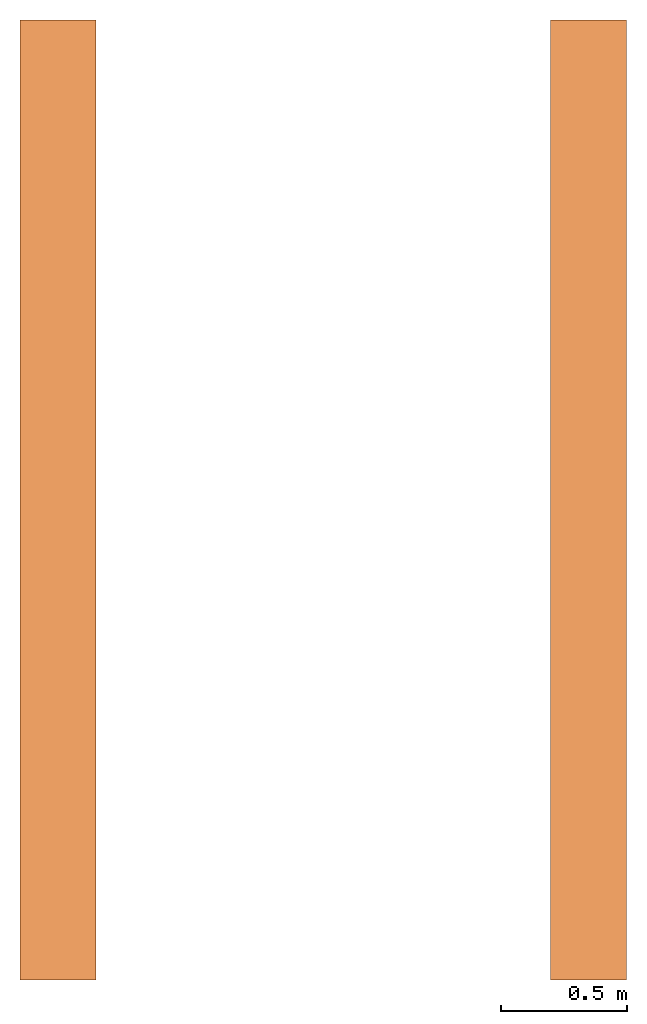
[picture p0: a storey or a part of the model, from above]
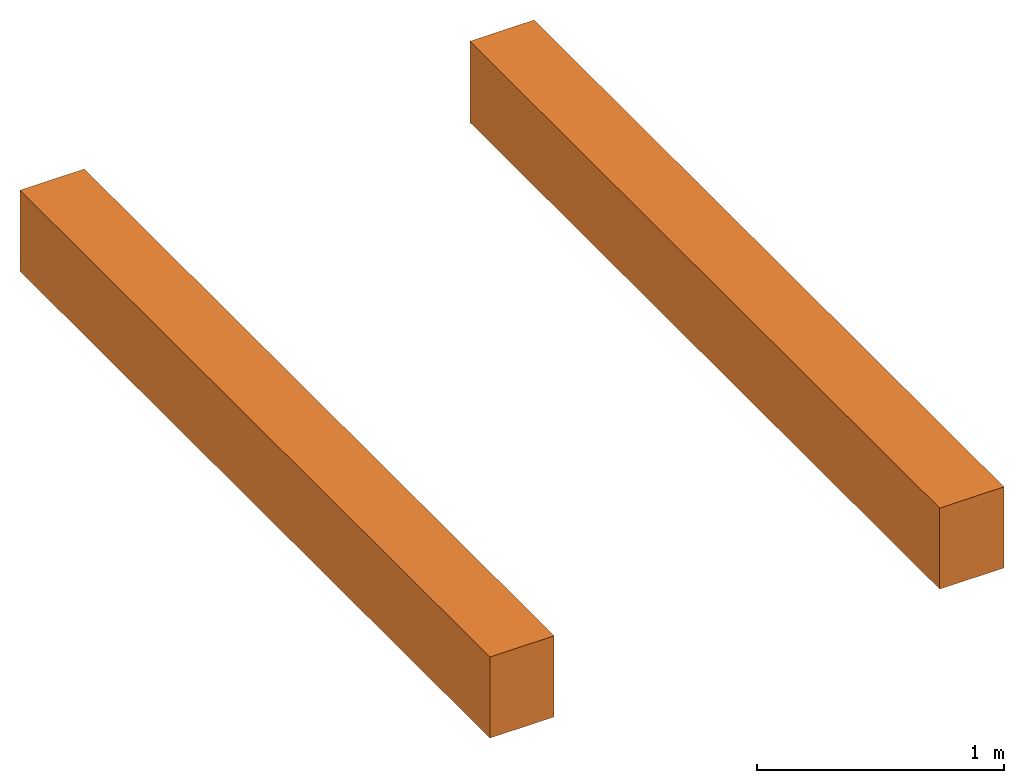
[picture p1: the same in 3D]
Properties of the parts of a building model (IFC2X3), part 1 of 2

# File
Description: ViewDefinition [CoordinationView_V2.0], RevitIdentifiers [ContentGUID: ca527c97-d4ec-411e-be0a-4f397f2c0beb, VersionGUID: 8476af31-6a10-44f1-af04-e6eb835c4134, NumberOfSaves: 289], CoordinateReference [CoordinateBase: Shared Coordinates]
File name: Sandbukta_vba_rvt2024.ifc
Time: 2026-06-26T07:16:23+01:00
Written by: ODA SDAI 24.6
Made in: Autodesk Revit 24.3.20.34 (ENU) - IFC 24.3.50.9

# IfcProject, 1350056494
LongName: Sandbukta VBA; Phase: Anbudsunderlag

# IfcSite, Default
RefLatitude: 59, 54, 44, 239196; RefLongitude: 10, 45, 0, 0; RefElevation: 0 mm

# IfcBuilding, Bygning (endres i Project Information)
LongName: Bygning (endres i Project Information)
Pset_BuildingCommon - NumberOfStoreys: 5

# IfcBuildingStorey: Level:NO_Nivå_Meter-VA (6)
In: Bygning (endres i Project Information)
Pset_AirSideSystemInformation - sets with these values: 2
Name | LongName = Name | Elevation (mm)
Plan U2 - Arbeid | Plan U2 - Arbeid | 11000
Plan U1 - Arbeid | Plan U1 - Arbeid | 14000
Plan arbeidsnivå | Plan arbeidsnivå | 16800
Plan 01 | Plan 01 | 19000
Plan Tak Lav | Plan Tak Lav | 22200
Plan Tak Høy | Plan Tak Høy | 24000

# IfcBuildingElementProxy: Blåsemaskin:Blåsemaskin, Blåsemaskin:Blåsemaskin:2688698
In: Plan 01
Type - Material: <Unnamed>
Pset_BuildingElementProxyCommon - Reference: Blåsemaskin; sets with these values: 2

# IfcBuildingElementProxy: Drenspumpe:Drenspumpe, Drenspumpe:Drenspumpe:2447455
In: Plan U2 - Arbeid
Type - Material: <Unnamed>
Pset_BuildingElementProxyCommon - Reference: Drenspumpe; sets with these values: 2

# IfcBuildingElementProxy: Membranrigg7:Membranrigg, Membranrigg7:Membranrigg:2422887
In: Plan 01
Type - Material: <Unnamed>
Pset_BuildingElementProxyCommon - Reference: Membranrigg; sets with these values: 2

# IfcBuildingElementProxy: Membranrigg8:Membranrigg, Membranrigg8:Membranrigg:2422900
In: Plan 01
Type - Material: <Unnamed>
Pset_BuildingElementProxyCommon - Reference: Membranrigg; sets with these values: 2

# IfcBuildingElementProxy: Overløpsrenne:Overløpsrenne, Overløpsrenne:Overløpsrenne:2651481
In: Plan arbeidsnivå
Type - Material: <Unnamed>
Pset_BuildingElementProxyCommon - Reference: Overløpsrenne; sets with these values: 2

# IfcBuildingElementProxy: Placeholder Luke:100x100cm (5)
In: Plan 01
Type - Material: Default luke
Pset_BuildingElementProxyCommon - Reference: 100x100cm; sets with these values: 2
Name (Placeholder Luke:100x100cm:...)
2450585
2450774
2452067
2452140
2452595

# IfcBuildingElementProxy: Placeholder Luke:200x100cm 2, Placeholder Luke:200x100cm 2:2452269
In: Plan 01
Type - Material: Default luke
Pset_BuildingElementProxyCommon - Reference: 200x100cm 2; sets with these values: 2

# IfcBuildingElementProxy: RNO_CoordinationColumns:RNO_Nullpunktssøyle, RNO_CoordinationColumns:RNO_Nullpunktssøyle:1821742
In: Plan 01
Type - Material: <Unnamed>
Pset_BuildingElementProxyCommon - Reference: RNO_Nullpunktssøyle; sets with these values: 2

# IfcBuildingElementProxy: RNO_CoordinationColumns:RNO_Rotasjonssøyle, RNO_CoordinationColumns:RNO_Rotasjonssøyle:1822006
In: Plan 01
Type - Material: <Unnamed>
Pset_BuildingElementProxyCommon - Reference: RNO_Rotasjonssøyle; sets with these values: 2

# IfcCovering: Basic Ceiling:Ceiling 1, Basic Ceiling:Ceiling 1:2464430
In: Plan 01
Type - PredefinedType: CEILING
Pset_CoveringCommon - Reference: Ceiling 1; sets with these values: 2

# IfcDistributionPort (880)
Description: Flow; FlowDirection: SOURCEANDSINK
Name | Group
Port_2536076_0 | 38= VanGen 2
Port_2536076_1 | 38= VanGen 2
Port_2546204_1 | 38= VanGen 2
Port_2537531_0 | 38= VanGen 2
Port_2688437_2 | 38= VanGen 2
Port_2537531_1 | 38= VanGen 2
Port_2540515_0 | 38= VanGen 3
Port_2650541_1 | 38= VanGen 3
Port_2540515_1 | 38= VanGen 3
Port_2650521_2 | 38= VanGen 3
Port_2544762_0 | 38= VanGen 12
Port_2700529_2 | 38= VanGen 12
Port_2544762_1 | 38= VanGen 12
Port_2700532_2 | 38= VanGen 12
Port_2544801_0 | 38= VanGen 12
Port_2700383_2 | 38= VanGen 12
Port_2544801_1 | 38= VanGen 12
Port_2700387_2 | 38= VanGen 12
Port_2544820_0 | 38= VanGen 12
Port_2700427_2 | 38= VanGen 12
Port_2544820_1 | 38= VanGen 12
Port_2700532_1 | 38= VanGen 12
Port_2546194_0 | 38= VanGen 2
Port_2546204_2 | 38= VanGen 2
Port_2546194_1 | 38= VanGen 2
Port_2546223_1 | 38= VanGen 2
Port_2546223_2 | 38= VanGen 2
Port_2552720_0 | 38= VanGen 2
Port_2547577_0 | 38= VanGen 10
Port_2675238_2 | 38= VanGen 10
Port_2547577_1 | 38= VanGen 10
Port_2675234_3 | 38= VanGen 10
Port_2547586_0 | 38= VanGen 10
Port_2675234_1 | 38= VanGen 10
Port_2547586_1 | 38= VanGen 10
Port_2547589_0 | 38= VanGen 10
Port_2675238_1 | 38= VanGen 10
Port_2547589_1 | 38= VanGen 10
Port_2548496_1 | 38= VanGen 12
Port_2665847_1 | 38= VanGen 12
Port_2548496_2 | 38= VanGen 12
Port_2664733_0 | 38= VanGen 12
Port_2552383_0 | 38= VanGen 2
Port_2614677_2 | 38= VanGen 2
Port_2552383_1 | 38= VanGen 2
Port_2552391_0 | 38= VanGen 2
Port_2614677_1 | 38= VanGen 2
Port_2552391_1 | 38= VanGen 2
Port_2552431_1 | 38= VanGen 2
Port_2552431_2 | 38= VanGen 2
Port_2552611_0 | 38= VanGen 2
Port_2552594_0 | 38= VanGen 2
Port_2552594_1 | 38= VanGen 2
Port_2552614_1 | 38= VanGen 2
Port_2552600_0 | 38= VanGen 2
Port_2552610_3 | 38= VanGen 2
Port_2552600_1 | 38= VanGen 2
Port_2552614_2 | 38= VanGen 2
Port_2552610_1 | 38= VanGen 2
Port_2552646_0 | 38= VanGen 2
Port_2552610_2 | 38= VanGen 2
Port_2552611_1 | 38= VanGen 2
Port_2552646_1 | 38= VanGen 2
Port_2687460_2 | 38= VanGen 2
Port_2552701_0 | 38= VanGen 2
Port_2552701_1 | 38= VanGen 2
Port_2552723_1 | 38= VanGen 2
Port_2552709_0 | 38= VanGen 2
Port_2552719_3 | 38= VanGen 2
Port_2552709_1 | 38= VanGen 2
Port_2552723_2 | 38= VanGen 2
Port_2552719_1 | 38= VanGen 2
Port_2552744_0 | 38= VanGen 2
Port_2552719_2 | 38= VanGen 2
Port_2552720_1 | 38= VanGen 2
Port_2552744_1 | 38= VanGen 2
Port_2687491_2 | 38= VanGen 2
Port_2575566_1 | 38= VanGen 12
Port_2674205_0 | 38= VanGen 12
Port_2575566_2 | 38= VanGen 10
Port_2691959_0 | 38= VanGen 10
Port_2575646_1 | 38= VanGen 12
Port_2687347_1 | 38= VanGen 12
Port_2575646_2 | 38= VanGen 10
Port_2591716_1 | 38= VanGen 10
Port_2577438_0 | 38= VanGen 12
Port_2665857_1 | 38= VanGen 12
Port_2577438_1 | 38= VanGen 12
Port_2693313_1 | 38= VanGen 12
Port_2577880_0 | 38= VanGen 12
Port_2607326_3 | 38= VanGen 12
Port_2577880_1 | 38= VanGen 12
Port_2687622_1 | 38= VanGen 12
Port_2578370_0 | 38= VanGen 12
Port_2606716_3 | 38= VanGen 12
Port_2578370_1 | 38= VanGen 12
Port_2664752_2 | 38= VanGen 12
Port_2580642_0 | 38= VanGen 12
Port_2652849_3 | 38= VanGen 12
Port_2580642_1 | 38= VanGen 12
Port_2654699_2 | 38= VanGen 12
Port_2581805_1 | 38= VanGen 12
Port_2672550_0 | 38= VanGen 12
Port_2581805_2 | 38= VanGen 12
Port_2667935_0 | 38= VanGen 12
Port_2582544_0 | 38= VanGen 12
Port_2667953_2 | 38= VanGen 12
Port_2582544_1 | 38= VanGen 12
Port_2583761_0 | 38= VanGen 2
Port_2640558_3 | 38= VanGen 2
Port_2583761_1 | 38= VanGen 2
Port_2591318_1 | 38= VanGen 10
Port_2591716_0 | 38= VanGen 10
Port_2591318_2 | 38= VanGen 10
Port_2597341_0 | 38= VanGen 10
Port_2593074_1 | 38= VanGen 12
Port_2674287_0 | 38= VanGen 12
Port_2593074_2 | 38= VanGen 10
Port_2691846_0 | 38= VanGen 10
Port_2596068_0 | 38= VanGen 12
Port_2685189_1 | 38= VanGen 12
Port_2596068_1 | 38= VanGen 12
Port_2679826_1 | 38= VanGen 12
Port_2596991_1 | 38= VanGen 12
Port_2687347_0 | 38= VanGen 12
Port_2596991_2 | 38= VanGen 12
Port_2686093_0 | 38= VanGen 12
Port_2597341_1 | 38= VanGen 10
Port_2673101_2 | 38= VanGen 10
Port_2597540_0 | 38= VanGen 10
Port_2673212_1 | 38= VanGen 10
Port_2597540_1 | 38= VanGen 10
Port_2673101_1 | 38= VanGen 10
Port_2603713_0 | 38= VanGen 12
Port_2644982_1 | 38= VanGen 12
Port_2603713_1 | 38= VanGen 12
Port_2644952_2 | 38= VanGen 12
Port_2603943_0 | 38= VanGen 12
Port_2644952_1 | 38= VanGen 12
Port_2603943_1 | 38= VanGen 12
Port_2604006_0 | 38= VanGen 12
Port_2644982_3 | 38= VanGen 12
Port_2604006_1 | 38= VanGen 12
Port_2604115_0 | 38= VanGen 12
Port_2660876_1 | 38= VanGen 12
Port_2604115_1 | 38= VanGen 12
Port_2606716_1 | 38= VanGen 12
Port_2624770_0 | 38= VanGen 12
Port_2606716_2 | 38= VanGen 12
Port_2607271_1 | 38= VanGen 12
Port_2607271_0 | 38= VanGen 12
Port_2607326_1 | 38= VanGen 12
Port_2607326_2 | 38= VanGen 12
Port_2607327_1 | 38= VanGen 12
Port_2607327_0 | 38= VanGen 12
Port_2697108_2 | 38= VanGen 12
Port_2613303_0 | 38= VanGen 12
Port_2661276_2 | 38= VanGen 12
Port_2613303_1 | 38= VanGen 12
Port_2660429_1 | 38= VanGen 12
Port_2614907_0 | 38= VanGen 2
Port_2664062_1 | 38= VanGen 2
Port_2614907_1 | 38= VanGen 2
Port_2615759_0 | 38= VanGen 13
Port_2615855_2 | 38= VanGen 13
Port_2615759_1 | 38= VanGen 13
Port_2615855_1 | 38= VanGen 13
Port_2697217_0 | 38= VanGen 13
Port_2615947_0 | 38= VanGen 13
Port_2697216_3 | 38= VanGen 13
Port_2615947_1 | 38= VanGen 13
Port_2624770_1 | 38= VanGen 12
Port_2660160_1 | 38= VanGen 12
Port_2625059_0 | 38= VanGen 12
Port_2652849_1 | 38= VanGen 12
Port_2625059_1 | 38= VanGen 12
Port_2658873_2 | 38= VanGen 12
Port_2626285_0 | 38= VanGen 12
Port_2665902_1 | 38= VanGen 12
Port_2626285_1 | 38= VanGen 12
Port_2626406_3 | 38= VanGen 12
Port_2626365_0 | 38= VanGen 12
Port_2626406_1 | 38= VanGen 12
Port_2626365_1 | 38= VanGen 12
Port_2697056_1 | 38= VanGen 12
Port_2626406_2 | 38= VanGen 12
Port_2626407_0 | 38= VanGen 12
Port_2626407_1 | 38= VanGen 12
Port_2693313_2 | 38= VanGen 12
Port_2627121_0 | 38= VanGen 2
Port_2640846_1 | 38= VanGen 2
Port_2627121_1 | 38= VanGen 2
Port_2640684_1 | 38= VanGen 2
Port_2627847_0 | 38= VanGen 2
Port_2687460_1 | 38= VanGen 2
Port_2627847_1 | 38= VanGen 2
Port_2688437_1 | 38= VanGen 2
Port_2628803_0 | 38= VanGen 2
Port_2640846_3 | 38= VanGen 2
Port_2628803_1 | 38= VanGen 2
Port_2635917_0 | 38= VanGen 9
Port_2662617_2 | 38= VanGen 9
Port_2635917_1 | 38= VanGen 9
Port_2639571_1 | 38= VanGen 12
Port_2639667_0 | 38= VanGen 12
Port_2639571_2 | 38= VanGen 12
Port_2639572_0 | 38= VanGen 12
Port_2639571_3 | 38= VanGen 12
Port_2661277_0 | 38= VanGen 12
Port_2639572_1 | 38= VanGen 12
Port_2660199_2 | 38= VanGen 12
Port_2639667_1 | 38= VanGen 12
Port_2696457_3 | 38= VanGen 12
Port_2639934_0 | 38= VanGen 2
Port_2640558_1 | 38= VanGen 2
Port_2639934_1 | 38= VanGen 2
Port_2640680_1 | 38= VanGen 2
Port_2640178_0 | 38= VanGen 2
Port_2640680_2 | 38= VanGen 2
Port_2640178_1 | 38= VanGen 2
Port_2640684_2 | 38= VanGen 2
Port_2640558_2 | 38= VanGen 2
Port_2640559_1 | 38= VanGen 2
Port_2640559_0 | 38= VanGen 2
Port_2640846_2 | 38= VanGen 2
Port_2643673_1 | 38= VanGen 2
Port_2640941_0 | 38= VanGen 12
Port_2640941_1 | 38= VanGen 12
Port_2683961_1 | 38= VanGen 12
Port_2641042_0 | 38= VanGen 12
Port_2641042_1 | 38= VanGen 12
Port_2642342_1 | 38= VanGen 12
Port_2641110_0 | 38= VanGen 12
Port_2683961_2 | 38= VanGen 12
Port_2641110_1 | 38= VanGen 12
Port_2683965_3 | 38= VanGen 12
Port_2642318_0 | 38= VanGen 12
Port_2642342_2 | 38= VanGen 12
Port_2642318_1 | 38= VanGen 12
Port_2686490_1 | 38= VanGen 12
Port_2642997_0 | 38= VanGen 2
Port_2687491_1 | 38= VanGen 2
Port_2642997_1 | 38= VanGen 2
Port_2643685_1 | 38= VanGen 2
Port_2643010_0 | 38= VanGen 2
Port_2643685_2 | 38= VanGen 2
Port_2643010_1 | 38= VanGen 2
Port_2664070_1 | 38= VanGen 2
Port_2643394_0 | 38= VanGen 1
Port_2643394_1 | 38= VanGen 1
Port_2643412_2 | 38= VanGen 1
Port_2643402_0 | 38= VanGen 1
Port_2643412_1 | 38= VanGen 1
Port_2643402_1 | 38= VanGen 1
Port_2643476_0 | 38= VanGen 5
Port_2681634_2 | 38= VanGen 5
Port_2643476_1 | 38= VanGen 5
Port_2682010_1 | 38= VanGen 5
Port_2643673_0 | 38= VanGen 2
Port_2663745_1 | 38= VanGen 2
Port_2644982_2 | 38= VanGen 12
Port_2644983_0 | 38= VanGen 12
Port_2644983_1 | 38= VanGen 12
Port_2660876_3 | 38= VanGen 12
Port_2648893_0 | 38= VanGen 12
Port_2658848_2 | 38= VanGen 12
Port_2648893_1 | 38= VanGen 12
Port_2649066_0 | 38= VanGen 12
Port_2661098_2 | 38= VanGen 12
Port_2649066_1 | 38= VanGen 12
Port_2649303_0 | 38= VanGen 12
Port_2700529_1 | 38= VanGen 12
Port_2649303_1 | 38= VanGen 12
Port_2661098_3 | 38= VanGen 12
Port_2649542_0 | 38= VanGen 12
Port_2694640_1 | 38= VanGen 12
Port_2649542_1 | 38= VanGen 12
Port_2658848_1 | 38= VanGen 12
Port_2650513_0 | 38= VanGen 3
Port_2650521_1 | 38= VanGen 3
Port_2650513_1 | 38= VanGen 3
Port_2650535_0 | 38= VanGen 3
Port_2650541_2 | 38= VanGen 3
Port_2650535_1 | 38= VanGen 3
Port_2652849_2 | 38= VanGen 12
Port_2696458_0 | 38= VanGen 12
Port_2653226_0 | 38= VanGen 12
Port_2656488_1 | 38= VanGen 12
Port_2653226_1 | 38= VanGen 12
Port_2656098_2 | 38= VanGen 12
Port_2654695_0 | 38= VanGen 12
Port_2654699_3 | 38= VanGen 12
Port_2654695_1 | 38= VanGen 12
Port_2654697_0 | 38= VanGen 12
Port_2654697_1 | 38= VanGen 12
Port_2654699_4 | 38= VanGen 12
Port_2654699_1 | 38= VanGen 12
Port_2654708_0 | 38= VanGen 12
Port_2654701_0 | 38= VanGen 12
Port_2654705_3 | 38= VanGen 12
Port_2654701_1 | 38= VanGen 12
Port_2654703_0 | 38= VanGen 12
Port_2654703_1 | 38= VanGen 12
Port_2654705_4 | 38= VanGen 12
Port_2654705_1 | 38= VanGen 12
Port_2654716_1 | 38= VanGen 12
Port_2654705_2 | 38= VanGen 12
Port_2654708_1 | 38= VanGen 12
Port_2654710_0 | 38= VanGen 12
Port_2654714_3 | 38= VanGen 12
Port_2654710_1 | 38= VanGen 12
Port_2654712_0 | 38= VanGen 12
Port_2654712_1 | 38= VanGen 12
Port_2654714_4 | 38= VanGen 12
Port_2654714_1 | 38= VanGen 12
Port_2654724_1 | 38= VanGen 12
Port_2654714_2 | 38= VanGen 12
Port_2654716_0 | 38= VanGen 12
Port_2654720_0 | 38= VanGen 12
Port_2654720_1 | 38= VanGen 12
Port_2654722_4 | 38= VanGen 12
Port_2654722_1 | 38= VanGen 12
Port_2654732_1 | 38= VanGen 12
Port_2654722_2 | 38= VanGen 12
Port_2654724_0 | 38= VanGen 12
Port_2654722_3 | 38= VanGen 12
Port_2656677_0 | 38= VanGen 12
Port_2654726_0 | 38= VanGen 12
Port_2654730_3 | 38= VanGen 12
Port_2654726_1 | 38= VanGen 12
Port_2654728_0 | 38= VanGen 12
Port_2654728_1 | 38= VanGen 12
Port_2654730_4 | 38= VanGen 12
Port_2654730_1 | 38= VanGen 12
Port_2654740_1 | 38= VanGen 12
Port_2654730_2 | 38= VanGen 12
Port_2654732_0 | 38= VanGen 12
Port_2654734_0 | 38= VanGen 12
Port_2654738_3 | 38= VanGen 12
Port_2654734_1 | 38= VanGen 12
Port_2654736_0 | 38= VanGen 12
Port_2654736_1 | 38= VanGen 12
Port_2654738_4 | 38= VanGen 12
Port_2654738_1 | 38= VanGen 12
Port_2654748_1 | 38= VanGen 12
Port_2654738_2 | 38= VanGen 12
Port_2654740_0 | 38= VanGen 12
Port_2654742_0 | 38= VanGen 12
Port_2654746_3 | 38= VanGen 12
Port_2654742_1 | 38= VanGen 12
Port_2654744_0 | 38= VanGen 12
Port_2654744_1 | 38= VanGen 12
Port_2654746_4 | 38= VanGen 12
Port_2654746_1 | 38= VanGen 12
Port_2654756_1 | 38= VanGen 12
Port_2654746_2 | 38= VanGen 12
Port_2654748_0 | 38= VanGen 12
Port_2654750_0 | 38= VanGen 12
Port_2654754_3 | 38= VanGen 12
Port_2654750_1 | 38= VanGen 12
Port_2654752_0 | 38= VanGen 12
Port_2654752_1 | 38= VanGen 12
Port_2654754_4 | 38= VanGen 12
Port_2654754_1 | 38= VanGen 12
Port_2654764_1 | 38= VanGen 12
Port_2654754_2 | 38= VanGen 12
Port_2654756_0 | 38= VanGen 12
Port_2654758_0 | 38= VanGen 12
Port_2654762_3 | 38= VanGen 12
Port_2654758_1 | 38= VanGen 12
Port_2654760_0 | 38= VanGen 12
Port_2654760_1 | 38= VanGen 12
Port_2654762_4 | 38= VanGen 12
Port_2654762_1 | 38= VanGen 12
Port_2654772_1 | 38= VanGen 12
Port_2654762_2 | 38= VanGen 12
Port_2654764_0 | 38= VanGen 12
Port_2654766_0 | 38= VanGen 12
Port_2654770_3 | 38= VanGen 12
Port_2654766_1 | 38= VanGen 12
Port_2654768_0 | 38= VanGen 12
Port_2654768_1 | 38= VanGen 12
Port_2654770_4 | 38= VanGen 12
Port_2654770_1 | 38= VanGen 12
Port_2654770_2 | 38= VanGen 12
Port_2654772_0 | 38= VanGen 12
Port_2655186_0 | 38= VanGen 14
Port_2655731_1 | 38= VanGen 14
Port_2655186_1 | 38= VanGen 14
Port_2655208_2 | 38= VanGen 14
Port_2655197_0 | 38= VanGen 14
Port_2655208_1 | 38= VanGen 14
Port_2655197_1 | 38= VanGen 14
Port_2655221_0 | 38= VanGen 14
Port_2655236_2 | 38= VanGen 14
Port_2655221_1 | 38= VanGen 14
Port_2655236_1 | 38= VanGen 14
Port_2655388_0 | 38= VanGen 14
Port_2655376_0 | 38= VanGen 14
Port_2655387_3 | 38= VanGen 14
Port_2655376_1 | 38= VanGen 14
Port_2655387_1 | 38= VanGen 14
Port_2655411_0 | 38= VanGen 14
Port_2655387_2 | 38= VanGen 14
Port_2655388_1 | 38= VanGen 14
Port_2655402_0 | 38= VanGen 14
Port_2655410_3 | 38= VanGen 14
Port_2655402_1 | 38= VanGen 14
Port_2655410_1 | 38= VanGen 14
Port_2655645_0 | 38= VanGen 14
Port_2655410_2 | 38= VanGen 14
Port_2655411_1 | 38= VanGen 14
Port_2655483_0 | 38= VanGen 14
Port_2655644_3 | 38= VanGen 14
Port_2655483_1 | 38= VanGen 14
Port_2655506_0 | 38= VanGen 14
Port_2655673_3 | 38= VanGen 14
Port_2655506_1 | 38= VanGen 14
Port_2655525_0 | 38= VanGen 14
Port_2655702_3 | 38= VanGen 14
Port_2655525_1 | 38= VanGen 14
Port_2655542_0 | 38= VanGen 14
Port_2655731_3 | 38= VanGen 14
Port_2655542_1 | 38= VanGen 14
Port_2655644_1 | 38= VanGen 14
Port_2655674_0 | 38= VanGen 14
Port_2655644_2 | 38= VanGen 14
Port_2655645_1 | 38= VanGen 14
Port_2655673_1 | 38= VanGen 14
Port_2655703_0 | 38= VanGen 14
Port_2655673_2 | 38= VanGen 14
Port_2655674_1 | 38= VanGen 14
Port_2655702_1 | 38= VanGen 14
Port_2655732_0 | 38= VanGen 14
Port_2655702_2 | 38= VanGen 14
Port_2655703_1 | 38= VanGen 14
Port_2655731_2 | 38= VanGen 14
Port_2655732_1 | 38= VanGen 14
Port_2656094_0 | 38= VanGen 12
Port_2656098_3 | 38= VanGen 12
Port_2656094_1 | 38= VanGen 12
Port_2656096_0 | 38= VanGen 12
Port_2656096_1 | 38= VanGen 12
Port_2656098_4 | 38= VanGen 12
Port_2656098_1 | 38= VanGen 12
Port_2656107_0 | 38= VanGen 12
Port_2656100_0 | 38= VanGen 12
Port_2656104_3 | 38= VanGen 12
Port_2656100_1 | 38= VanGen 12
Port_2656102_0 | 38= VanGen 12
Port_2656102_1 | 38= VanGen 12
Port_2656104_4 | 38= VanGen 12
Port_2656104_1 | 38= VanGen 12
Port_2656115_1 | 38= VanGen 12
Port_2656104_2 | 38= VanGen 12
Port_2656107_1 | 38= VanGen 12
Port_2656109_0 | 38= VanGen 12
Port_2656113_3 | 38= VanGen 12
Port_2656109_1 | 38= VanGen 12
Port_2656111_0 | 38= VanGen 12
Port_2656111_1 | 38= VanGen 12
Port_2656113_4 | 38= VanGen 12
Port_2656113_1 | 38= VanGen 12
Port_2656121_1 | 38= VanGen 12
Port_2656113_2 | 38= VanGen 12
Port_2656115_0 | 38= VanGen 12
Port_2656117_0 | 38= VanGen 12
Port_2656117_1 | 38= VanGen 12
Port_2656119_4 | 38= VanGen 12
Port_2656119_1 | 38= VanGen 12
Port_2656129_1 | 38= VanGen 12
Port_2656119_2 | 38= VanGen 12
Port_2656121_0 | 38= VanGen 12
Port_2656119_3 | 38= VanGen 12
Port_2656702_0 | 38= VanGen 12
Port_2656123_0 | 38= VanGen 12
Port_2656127_3 | 38= VanGen 12
Port_2656123_1 | 38= VanGen 12
Port_2656125_0 | 38= VanGen 12
Port_2656125_1 | 38= VanGen 12
Port_2656127_4 | 38= VanGen 12
Port_2656127_1 | 38= VanGen 12
Port_2656137_1 | 38= VanGen 12
Port_2656127_2 | 38= VanGen 12
Port_2656129_0 | 38= VanGen 12
Port_2656131_0 | 38= VanGen 12
Port_2656135_3 | 38= VanGen 12
Port_2656131_1 | 38= VanGen 12
Port_2656133_0 | 38= VanGen 12
Port_2656133_1 | 38= VanGen 12
Port_2656135_4 | 38= VanGen 12
Port_2656135_1 | 38= VanGen 12
Port_2656145_1 | 38= VanGen 12
Port_2656135_2 | 38= VanGen 12
Port_2656137_0 | 38= VanGen 12
Port_2656139_0 | 38= VanGen 12
Port_2656143_3 | 38= VanGen 12
Port_2656139_1 | 38= VanGen 12
Port_2656141_0 | 38= VanGen 12
Port_2656141_1 | 38= VanGen 12
Port_2656143_4 | 38= VanGen 12
Port_2656143_1 | 38= VanGen 12
Port_2656153_1 | 38= VanGen 12
Port_2656143_2 | 38= VanGen 12
Port_2656145_0 | 38= VanGen 12
Port_2656147_0 | 38= VanGen 12
Port_2656151_3 | 38= VanGen 12
Port_2656147_1 | 38= VanGen 12
Port_2656149_0 | 38= VanGen 12
Port_2656149_1 | 38= VanGen 12
Port_2656151_4 | 38= VanGen 12
Port_2656151_1 | 38= VanGen 12
Port_2656161_1 | 38= VanGen 12
Port_2656151_2 | 38= VanGen 12
Port_2656153_0 | 38= VanGen 12
Port_2656155_0 | 38= VanGen 12
Port_2656159_3 | 38= VanGen 12
Port_2656155_1 | 38= VanGen 12
Port_2656157_0 | 38= VanGen 12
Port_2656157_1 | 38= VanGen 12
Port_2656159_4 | 38= VanGen 12
Port_2656159_1 | 38= VanGen 12
Port_2656169_1 | 38= VanGen 12
Port_2656159_2 | 38= VanGen 12
Port_2656161_0 | 38= VanGen 12
Port_2656163_0 | 38= VanGen 12
Port_2656167_3 | 38= VanGen 12
Port_2656163_1 | 38= VanGen 12
Port_2656165_0 | 38= VanGen 12
Port_2656165_1 | 38= VanGen 12
Port_2656167_4 | 38= VanGen 12
Port_2656167_1 | 38= VanGen 12
Port_2656167_2 | 38= VanGen 12
Port_2656169_0 | 38= VanGen 12
Port_2656171_0 | 38= VanGen 37
Port_2656213_1 | 38= VanGen 37
Port_2656171_1 | 38= VanGen 37
Port_2656175_2 | 38= VanGen 37
Port_2656173_0 | 38= VanGen 37
Port_2656175_1 | 38= VanGen 37
Port_2656173_1 | 38= VanGen 37
Port_2656177_0 | 38= VanGen 37
Port_2656179_2 | 38= VanGen 37
Port_2656177_1 | 38= VanGen 37
Port_2656179_1 | 38= VanGen 37
Port_2656184_0 | 38= VanGen 37
Port_2656181_0 | 38= VanGen 37
Port_2656183_3 | 38= VanGen 37
Port_2656181_1 | 38= VanGen 37
Port_2656183_1 | 38= VanGen 37
Port_2656190_0 | 38= VanGen 37
Port_2656183_2 | 38= VanGen 37
Port_2656184_1 | 38= VanGen 37
Port_2656187_0 | 38= VanGen 37
Port_2656189_3 | 38= VanGen 37
Port_2656187_1 | 38= VanGen 37
Port_2656189_1 | 38= VanGen 37
Port_2656202_0 | 38= VanGen 37
Port_2656189_2 | 38= VanGen 37
Port_2656190_1 | 38= VanGen 37
Port_2656193_0 | 38= VanGen 37
Port_2656201_3 | 38= VanGen 37
Port_2656193_1 | 38= VanGen 37
Port_2656195_0 | 38= VanGen 37
Port_2656205_3 | 38= VanGen 37
Port_2656195_1 | 38= VanGen 37
Port_2656197_0 | 38= VanGen 37
Port_2656209_3 | 38= VanGen 37
Port_2656197_1 | 38= VanGen 37
Port_2656199_0 | 38= VanGen 37
Port_2656213_3 | 38= VanGen 37
Port_2656199_1 | 38= VanGen 37
Port_2656201_1 | 38= VanGen 37
Port_2656206_0 | 38= VanGen 37
Port_2656201_2 | 38= VanGen 37
Port_2656202_1 | 38= VanGen 37
Port_2656205_1 | 38= VanGen 37
Port_2656210_0 | 38= VanGen 37
Port_2656205_2 | 38= VanGen 37
Port_2656206_1 | 38= VanGen 37
Port_2656209_1 | 38= VanGen 37
Port_2656214_0 | 38= VanGen 37
Port_2656209_2 | 38= VanGen 37
Port_2656210_1 | 38= VanGen 37
Port_2656213_2 | 38= VanGen 37
Port_2656214_1 | 38= VanGen 37
Port_2656488_2 | 38= VanGen 12
Port_2658873_1 | 38= VanGen 12
Port_2656677_1 | 38= VanGen 12
Port_2656702_1 | 38= VanGen 12
Port_2660152_0 | 38= VanGen 12
Port_2660160_2 | 38= VanGen 12
Port_2660152_1 | 38= VanGen 12
Port_2660199_1 | 38= VanGen 12
Port_2660429_2 | 38= VanGen 12
Port_2660877_0 | 38= VanGen 12
Port_2660876_2 | 38= VanGen 12
Port_2660877_1 | 38= VanGen 12
Port_2661098_1 | 38= VanGen 12
Port_2661255_0 | 38= VanGen 12
Port_2661255_1 | 38= VanGen 12
Port_2688219_1 | 38= VanGen 12
Port_2661263_0 | 38= VanGen 12
Port_2688219_2 | 38= VanGen 12
Port_2661263_1 | 38= VanGen 12
Port_2688223_1 | 38= VanGen 12
Port_2661276_1 | 38= VanGen 12
Port_2661277_1 | 38= VanGen 12
Port_2661276_3 | 38= VanGen 12
Port_2688169_0 | 38= VanGen 12
Port_2662487_1 | 38= VanGen 5
Port_2663276_1 | 38= VanGen 5
Port_2662487_2 | 38= VanGen 9
Port_2662662_1 | 38= VanGen 9
Port_2662609_0 | 38= VanGen 9
Port_2663120_1 | 38= VanGen 9
Port_2662609_1 | 38= VanGen 9
Port_2662639_1 | 38= VanGen 9
Port_2662617_1 | 38= VanGen 9
Port_2663154_0 | 38= VanGen 9
Port_2662619_0 | 38= VanGen 9
Port_2662639_2 | 38= VanGen 9
Port_2662619_1 | 38= VanGen 9
Port_2669744_1 | 38= VanGen 9
Port_2662662_0 | 38= VanGen 9
Port_2669744_2 | 38= VanGen 9
Port_2662990_1 | 38= VanGen 5
Port_2670665_0 | 38= VanGen 5
Port_2662990_2 | 38= VanGen 9
Port_2662991_1 | 38= VanGen 9
Port_2662991_0 | 38= VanGen 9
Port_2663120_3 | 38= VanGen 9
Port_2663052_1 | 38= VanGen 5
Port_2671532_0 | 38= VanGen 5
Port_2663052_2 | 38= VanGen 9
Port_2663053_1 | 38= VanGen 9
Port_2663053_0 | 38= VanGen 9
Port_2663153_3 | 38= VanGen 9
Port_2663120_2 | 38= VanGen 9
Port_2663121_1 | 38= VanGen 9
Port_2663121_0 | 38= VanGen 9
Port_2663153_1 | 38= VanGen 9
Port_2663153_2 | 38= VanGen 9
Port_2663154_1 | 38= VanGen 9
Port_2663266_0 | 38= VanGen 5
Port_2663274_2 | 38= VanGen 5
Port_2663266_1 | 38= VanGen 5
Port_2669174_1 | 38= VanGen 5
Port_2663274_1 | 38= VanGen 5
Port_2663313_0 | 38= VanGen 5
Port_2663276_0 | 38= VanGen 5
Port_2672610_2 | 38= VanGen 5
Port_2663299_0 | 38= VanGen 5
Port_2663312_3 | 38= VanGen 5
Port_2663299_1 | 38= VanGen 5
Port_2670680_2 | 38= VanGen 5
Port_2663312_1 | 38= VanGen 5
Port_2663334_0 | 38= VanGen 5
Port_2663312_2 | 38= VanGen 5
Port_2663313_1 | 38= VanGen 5
Port_2663322_0 | 38= VanGen 5
Port_2663333_3 | 38= VanGen 5
Port_2663322_1 | 38= VanGen 5
Port_2671547_2 | 38= VanGen 5
Port_2663333_1 | 38= VanGen 5
Port_2681463_0 | 38= VanGen 5
Port_2663333_2 | 38= VanGen 5
Port_2663334_1 | 38= VanGen 5
Port_2663745_2 | 38= VanGen 2
Port_2664063_0 | 38= VanGen 2
Port_2664040_0 | 38= VanGen 2
Port_2664062_3 | 38= VanGen 2
Port_2664040_1 | 38= VanGen 2
Port_2664070_2 | 38= VanGen 2
Port_2664062_2 | 38= VanGen 2
Port_2664063_1 | 38= VanGen 2
Port_2664733_1 | 38= VanGen 12
Port_2664752_1 | 38= VanGen 12
Port_2665645_1 | 38= VanGen 12
Port_2665892_1 | 38= VanGen 12
Port_2665645_2 | 38= VanGen 12
Port_2687612_1 | 38= VanGen 12
Port_2665847_0 | 38= VanGen 12
Port_2665857_2 | 38= VanGen 12
Port_2665892_0 | 38= VanGen 12
Port_2665902_2 | 38= VanGen 12
Port_2667935_1 | 38= VanGen 12
Port_2667953_1 | 38= VanGen 12
Port_2668036_0 | 38= VanGen 12
Port_2672565_2 | 38= VanGen 12
Port_2668036_1 | 38= VanGen 12
Port_2668100_1 | 38= VanGen 12
Port_2668100_2 | 38= VanGen 12
Port_2668130_0 | 38= VanGen 12
Port_2668130_1 | 38= VanGen 12
Port_2668176_1 | 38= VanGen 12
Port_2668176_2 | 38= VanGen 12
Port_2668214_0 | 38= VanGen 12
Port_2668214_1 | 38= VanGen 12
Port_2668263_1 | 38= VanGen 12
Port_2668222_0 | 38= VanGen 12
Port_2668263_2 | 38= VanGen 12
Port_2668222_1 | 38= VanGen 12
Port_2696363_1 | 38= VanGen 12
Port_2669174_2 | 38= VanGen 5
Port_2672610_1 | 38= VanGen 5
Port_2670665_1 | 38= VanGen 5
Port_2670680_1 | 38= VanGen 5
Port_2671532_1 | 38= VanGen 5
Port_2671547_1 | 38= VanGen 5
Port_2672550_1 | 38= VanGen 12
Port_2672565_1 | 38= VanGen 12
Port_2673212_2 | 38= VanGen 10
Port_2673213_1 | 38= VanGen 10
Port_2673212_3 | 38= VanGen 10
Port_2691973_2 | 38= VanGen 10
Port_2673213_0 | 38= VanGen 10
Port_2699155_1 | 38= VanGen 10
Port_2674205_1 | 38= VanGen 12
Port_2679826_2 | 38= VanGen 12
Port_2674287_1 | 38= VanGen 12
Port_2679914_1 | 38= VanGen 12
Port_2675234_2 | 38= VanGen 10
Port_2691334_0 | 38= VanGen 10
Port_2675235_0 | 38= VanGen 10
Port_2699155_2 | 38= VanGen 10
Port_2675235_1 | 38= VanGen 10
Port_2698856_1 | 38= VanGen 10
Port_2678810_0 | 38= VanGen 12
Port_2697108_1 | 38= VanGen 12
Port_2678810_1 | 38= VanGen 12
Port_2697110_3 | 38= VanGen 12
Port_2679422_0 | 38= VanGen 12
Port_2686092_2 | 38= VanGen 12
Port_2679422_1 | 38= VanGen 12
Port_2685428_3 | 38= VanGen 12
Port_2679887_0 | 38= VanGen 12
Port_2679914_2 | 38= VanGen 12
Port_2679887_1 | 38= VanGen 12
Port_2685743_1 | 38= VanGen 12
Port_2681463_1 | 38= VanGen 5
Port_2681631_2 | 38= VanGen 5
Port_2681469_0 | 38= VanGen 5
Port_2681631_1 | 38= VanGen 5
Port_2681469_1 | 38= VanGen 5
Port_2681634_1 | 38= VanGen 5
Port_2682002_0 | 38= VanGen 5
Port_2682010_2 | 38= VanGen 5
Port_2682002_1 | 38= VanGen 5
Port_2682055_1 | 38= VanGen 5
Port_2682047_0 | 38= VanGen 5
Port_2682055_2 | 38= VanGen 5
Port_2682047_1 | 38= VanGen 5
Port_2683953_0 | 38= VanGen 12
Port_2683965_1 | 38= VanGen 12
Port_2683953_1 | 38= VanGen 12
Port_2697060_1 | 38= VanGen 12
Port_2683965_2 | 38= VanGen 12
Port_2683966_0 | 38= VanGen 12
Port_2683966_1 | 38= VanGen 12
Port_2686492_2 | 38= VanGen 12
Port_2684362_0 | 38= VanGen 12
Port_2700427_1 | 38= VanGen 12
Port_2684362_1 | 38= VanGen 12
Port_2701886_1 | 38= VanGen 12
Port_2685189_2 | 38= VanGen 12
Port_2685375_1 | 38= VanGen 12
Port_2685375_0 | 38= VanGen 12
Port_2685428_1 | 38= VanGen 12
Port_2685428_2 | 38= VanGen 12
Port_2701950_0 | 38= VanGen 12
Port_2685596_0 | 38= VanGen 12
Port_2686092_3 | 38= VanGen 12
Port_2685596_1 | 38= VanGen 12
Port_2686098_3 | 38= VanGen 12
Port_2685735_0 | 38= VanGen 12
Port_2685743_2 | 38= VanGen 12
Port_2685735_1 | 38= VanGen 12
Port_2685952_2 | 38= VanGen 12
Port_2685952_1 | 38= VanGen 12
Port_2686099_0 | 38= VanGen 12
Port_2686092_1 | 38= VanGen 12
Port_2686093_1 | 38= VanGen 12
Port_2686098_1 | 38= VanGen 12
Port_2701955_0 | 38= VanGen 12
Port_2686098_2 | 38= VanGen 12
Port_2686099_1 | 38= VanGen 12
Port_2686295_0 | 38= VanGen 12
Port_2700383_1 | 38= VanGen 12
Port_2686295_1 | 38= VanGen 12
Port_2686415_2 | 38= VanGen 12
Port_2686415_1 | 38= VanGen 12
Port_2701537_1 | 38= VanGen 12
Port_2686490_2 | 38= VanGen 12
Port_2686492_1 | 38= VanGen 12
Port_2686656_0 | 38= VanGen 12
Port_2697110_2 | 38= VanGen 12
Port_2686656_1 | 38= VanGen 12
Port_2697060_2 | 38= VanGen 12
Port_2687612_0 | 38= VanGen 12
Port_2687622_2 | 38= VanGen 12
Port_2688169_1 | 38= VanGen 12
Port_2688223_2 | 38= VanGen 12
Port_2688772_0 | 38= VanGen 13
Port_2699723_2 | 38= VanGen 13
Port_2688772_1 | 38= VanGen 13
Port_2699800_1 | 38= VanGen 13
Port_2689823_0 | 38= VanGen 4
Port_2689823_1 | 38= VanGen 4
Port_2689839_1 | 38= VanGen 4
Port_2689831_0 | 38= VanGen 4
Port_2689839_2 | 38= VanGen 4
Port_2689831_1 | 38= VanGen 4
Port_2690133_0 | 38= VanGen 7
Port_2690133_1 | 38= VanGen 7
Port_2690137_1 | 38= VanGen 7
Port_2690135_0 | 38= VanGen 7
Port_2690137_2 | 38= VanGen 7
Port_2690135_1 | 38= VanGen 7
Port_2691334_1 | 38= VanGen 10
Port_2698856_2 | 38= VanGen 10
Port_2691846_1 | 38= VanGen 10
Port_2691959_1 | 38= VanGen 10
Port_2691973_1 | 38= VanGen 10
Port_2694143_0 | 38= VanGen 12
Port_2694640_2 | 38= VanGen 12
Port_2694143_1 | 38= VanGen 12
Port_2700387_1 | 38= VanGen 12
Port_2696363_2 | 38= VanGen 12
Port_2696448_1 | 38= VanGen 12
Port_2696448_0 | 38= VanGen 12
Port_2696457_1 | 38= VanGen 12
Port_2696457_2 | 38= VanGen 12
Port_2696458_1 | 38= VanGen 12
Port_2696830_0 | 38= VanGen 13
Port_2699723_1 | 38= VanGen 13
Port_2696830_1 | 38= VanGen 13
Port_2697017_1 | 38= VanGen 13
Port_2697009_0 | 38= VanGen 13
Port_2697017_2 | 38= VanGen 13
Port_2697009_1 | 38= VanGen 13
Port_2697056_2 | 38= VanGen 12
Port_2697111_0 | 38= VanGen 12
Port_2697110_1 | 38= VanGen 12
Port_2697111_1 | 38= VanGen 12
Port_2697216_1 | 38= VanGen 13
Port_2697363_0 | 38= VanGen 13
Port_2697216_2 | 38= VanGen 13
Port_2697217_1 | 38= VanGen 13
Port_2697363_1 | 38= VanGen 13
Port_2700258_1 | 38= VanGen 13
Port_2698803_1 | 38= VanGen 10
Port_2698803_2 | 38= VanGen 10
Port_2698856_3 | 38= VanGen 10
Port_2699792_0 | 38= VanGen 13
Port_2699800_2 | 38= VanGen 13
Port_2699792_1 | 38= VanGen 13
Port_2699900_1 | 38= VanGen 13
Port_2699900_2 | 38= VanGen 13
Port_2700201_0 | 38= VanGen 13
Port_2700201_1 | 38= VanGen 13
Port_2700254_1 | 38= VanGen 13
Port_2700209_0 | 38= VanGen 13
Port_2700254_2 | 38= VanGen 13
Port_2700209_1 | 38= VanGen 13
Port_2700258_2 | 38= VanGen 13
Port_2701537_0 | 38= VanGen 12
Port_2701954_1 | 38= VanGen 12
Port_2701886_2 | 38= VanGen 12
Port_2701923_1 | 38= VanGen 12
Port_2701914_0 | 38= VanGen 12
Port_2701949_3 | 38= VanGen 12
Port_2701914_1 | 38= VanGen 12
Port_2701954_3 | 38= VanGen 12
Port_2701923_0 | 38= VanGen 12
Port_2701949_1 | 38= VanGen 12
Port_2701949_2 | 38= VanGen 12
Port_2701950_1 | 38= VanGen 12
Port_2701954_2 | 38= VanGen 12
Port_2701955_1 | 38= VanGen 12

# IfcDoor: Double Door Simple:1930mm x 2184mm - ion alu (2)
In: Plan 01
Type - ParameterTakesPrecedence: no; Sizeable: no; Material: Door - Hardware, Door - H.M. Panel, Door - H.M. Frame
OverallHeight: 2184.4 mm; OverallWidth: 1930.4 mm
Pset_DoorCommon - IsExternal: no; Reference: 1930mm x 2184mm - ion alu
Pset_QuantityTakeOff - Reference: 1930mm x 2184mm - ion alu
Name (Double Door Simple:1930mm x 2184mm - ion alu:...)
2422955
2433673

# IfcDoor: Garage dooor/gate:2600x2400mm, Garage dooor/gate:2600x2400mm:2499129
In: Plan 01
Type - ParameterTakesPrecedence: no; Sizeable: no; Material: Garage Door - Panel, Garage Door - Jamb
OverallHeight: 2400 mm; OverallWidth: 2600 mm
Pset_DoorCommon - IsExternal: yes; Reference: 2600x2400mm
Pset_QuantityTakeOff - Reference: 2600x2400mm

# IfcDoor: Garage dooor/gate:3000x3600mm 3, Garage dooor/gate:3000x3600mm 3:2422937
In: Plan 01
Type - ParameterTakesPrecedence: no; Sizeable: no; Material: Garage Door - Panel, Garage Door - Jamb
Type - Pset_ManufacturerTypeInformation - Manufacturer: Fabio Loretti
OverallHeight: 3600 mm; OverallWidth: 3000 mm
Pset_DoorCommon - IsExternal: yes; Reference: 3000x3600mm 3
Pset_QuantityTakeOff - Reference: 3000x3600mm 3

# IfcDoor: Single Door Simple:886 x 2089 mm - M9 x M21, Single Door Simple:886 x 2089 mm - M9 x M21:2432995
In: Plan 01
Type - OperationType: SINGLE_SWING_LEFT; ParameterTakesPrecedence: no; Sizeable: no; Material: Titanium, Wood (Oak), RAL 9010, <Unnamed>
Type - Single Door Simple:886 x 2089 mm - M9 x M21:2432995:1 - PanelOperation: SWINGING
Type - Pset_ManufacturerTypeInformation - Manufacturer: JELD-WEN
OverallHeight: 2101 mm; OverallWidth: 910 mm
Pset_DoorCommon - IsExternal: no; Reference: 886 x 2089 mm - M9 x M21
Pset_FireRatingProperties - FireResistanceRating: EI60 (BD60)
Pset_QuantityTakeOff - Reference: 886 x 2089 mm - M9 x M21

# IfcDoor: Single Door Simple:886 x 2089 mm - M9 x M21 (4)
In: Plan 01
Type - OperationType: SINGLE_SWING_RIGHT; ParameterTakesPrecedence: no; Sizeable: no; Material: Titanium, Wood (Oak), RAL 9010, <Unnamed>
Type - Single Door Simple:886 x 2089 mm - M9 x M21:2429868:1 - PanelOperation: SWINGING
Type - Pset_ManufacturerTypeInformation - Manufacturer: JELD-WEN
OverallHeight: 2101 mm; OverallWidth: 910 mm
Pset_DoorCommon - IsExternal: no; Reference: 886 x 2089 mm - M9 x M21
Pset_FireRatingProperties - FireResistanceRating: EI60 (BD60)
Pset_QuantityTakeOff - Reference: 886 x 2089 mm - M9 x M21
Name (Single Door Simple:886 x 2089 mm - M9 x M21:...)
2429868
2432924
2502379
2507334

# IfcDoor: Single Door Simple:986 x 2089 mm - M10 x M21, Single Door Simple:986 x 2089 mm - M10 x M21:2496062
In: Plan 01
Type - OperationType: SINGLE_SWING_LEFT; ParameterTakesPrecedence: no; Sizeable: no; Material: Titanium, Wood (Oak), RAL 9010, <Unnamed>
Type - Single Door Simple:986 x 2089 mm - M10 x M21:2496062:1 - PanelOperation: SWINGING
Type - Pset_ManufacturerTypeInformation - Manufacturer: JELD-WEN
OverallHeight: 2101 mm; OverallWidth: 1010 mm
Pset_DoorCommon - IsExternal: no; Reference: 986 x 2089 mm - M10 x M21
Pset_FireRatingProperties - FireResistanceRating: EI60 (BD60)
Pset_QuantityTakeOff - Reference: 986 x 2089 mm - M10 x M21

# IfcDoor: Single Door Simple:986 x 2089 mm - M10 x M21, Single Door Simple:986 x 2089 mm - M10 x M21:2498785
In: Plan 01
Type - OperationType: SINGLE_SWING_LEFT; ParameterTakesPrecedence: no; Sizeable: no; Material: Titanium, Wood (Oak), RAL 9010, <Unnamed>
Type - Single Door Simple:986 x 2089 mm - M10 x M21:2498785:1 - PanelOperation: SWINGING
Type - Pset_ManufacturerTypeInformation - Manufacturer: JELD-WEN
OverallHeight: 2101 mm; OverallWidth: 1010 mm
Pset_DoorCommon - IsExternal: no; Reference: 986 x 2089 mm - M10 x M21
Pset_FireRatingProperties - FireResistanceRating: EI60 (BD60)
Pset_QuantityTakeOff - Reference: 986 x 2089 mm - M10 x M21

# IfcDoor: Single Door Simple:986 x 2089 mm - M10 x M21 (3)
In: Plan 01
Type - OperationType: SINGLE_SWING_RIGHT; ParameterTakesPrecedence: no; Sizeable: no; Material: Titanium, Wood (Oak), RAL 9010, <Unnamed>
Type - Single Door Simple:986 x 2089 mm - M10 x M21:2429803:1 - PanelOperation: SWINGING
Type - Pset_ManufacturerTypeInformation - Manufacturer: JELD-WEN
OverallHeight: 2101 mm; OverallWidth: 1010 mm
Pset_DoorCommon - IsExternal: no; Reference: 986 x 2089 mm - M10 x M21
Pset_FireRatingProperties - FireResistanceRating: EI60 (BD60)
Pset_QuantityTakeOff - Reference: 986 x 2089 mm - M10 x M21
Name (Single Door Simple:986 x 2089 mm - M10 x M21:...)
2429803
2432875
2432963

# IfcDoor: Single Door Simple:986 x 2089 mm - M10 x M21 (2)
In: Plan 01
Type - OperationType: SINGLE_SWING_RIGHT; ParameterTakesPrecedence: no; Sizeable: no; Material: Titanium, Wood (Oak), RAL 9010, <Unnamed>
Type - Single Door Simple:986 x 2089 mm - M10 x M21:2429828:1 - PanelOperation: SWINGING
Type - Pset_ManufacturerTypeInformation - Manufacturer: JELD-WEN
OverallHeight: 2101 mm; OverallWidth: 1010 mm
Pset_DoorCommon - IsExternal: no; Reference: 986 x 2089 mm - M10 x M21
Pset_FireRatingProperties - FireResistanceRating: EI60 (BD60)
Pset_QuantityTakeOff - Reference: 986 x 2089 mm - M10 x M21
Name (Single Door Simple:986 x 2089 mm - M10 x M21:...)
2429828
2454157

# IfcDoor: Single Door Simple:986 x 2089 mm - M10 x M21 (4)
In: Plan 01
Type - OperationType: SINGLE_SWING_RIGHT; ParameterTakesPrecedence: no; Sizeable: no; Material: Titanium, Wood (Oak), RAL 9010, <Unnamed>
Type - Single Door Simple:986 x 2089 mm - M10 x M21:2432838:1 - PanelOperation: SWINGING
Type - Pset_ManufacturerTypeInformation - Manufacturer: JELD-WEN
OverallHeight: 2101 mm; OverallWidth: 1010 mm
Pset_DoorCommon - IsExternal: no; Reference: 986 x 2089 mm - M10 x M21
Pset_FireRatingProperties - FireResistanceRating: EI60 (BD60)
Pset_QuantityTakeOff - Reference: 986 x 2089 mm - M10 x M21
Name (Single Door Simple:986 x 2089 mm - M10 x M21:...)
2432838
2433603
2496106
2497734

# IfcFlowController: Flow Arrow 3D:Lengde 300 (2)
In: Plan U1 - Arbeid
Type - Material: Flow Pil
Pset_DistributionFlowElementCommon - Reference: Lengde 300; sets with these values: 2
Name (Flow Arrow 3D:Lengde 300:...)
2700723
2702097

# IfcFlowController: NK 150-315_SS_F_FWOSPACER_INNOMOTICS_IE4_50HZ_4P_37KW:NK 150-315_SS_F_FWOSPACER_INNOMOTICS_IE4_50HZ_4P_37KW, NK 150-315_SS_F_FWOSPACER_INNOMOTICS_IE4_50HZ_4P_37KW:NK 150-315_SS_F_FWOSPACER_INNOMOTICS_IE4_50HZ_4P_37KW:2581805
In: Plan U1 - Arbeid
Type - Material: SS 2343 Rustfritt stål, prosessrør, generisk
Pset_DistributionFlowElementCommon - Reference: NK 150-315_SS_F_FWOSPACER_INNOMOTICS_IE4_50HZ_4P_37KW; sets with these values: 2
Group: 38= VanGen 12

# IfcFlowController: NK 32-250 262 AA1F2AESBQQENW1:NK 32-250 262 AA1F2AESBQQENW1 (3)
In: Plan U1 - Arbeid
Type - Material: SS 2343 Rustfritt stål, prosessrør, generisk
Pset_DistributionFlowElementCommon - Reference: NK 32-250 262 AA1F2AESBQQENW1; sets with these values: 2
Group: 38= VanGen 9; 38= VanGen 5
Name (NK 32-250 262 AA1F2AESBQQENW1:NK 32-250 262 AA1F2AESBQQENW1:...)
2662487
2662990
2663052

# IfcFlowController: Spektron 400e DN300 PN16 NW (3D):Spektron 400e DN300 PN16 NW (3D) (2)
In: Plan U1 - Arbeid
Type - Material: SS 2343 Rustfritt stål, prosessrør, generisk
Pset_DistributionFlowElementCommon - Reference: Spektron 400e DN300 PN16 NW (3D); sets with these values: 2
Group: 38= VanGen 12
Name (Spektron 400e DN300 PN16 NW (3D):Spektron 400e DN300 PN16 NW (3D):...)
2548496
2665645

# IfcFlowController: nk-50-250263:nk-50-250263 (3)
In: Plan U2 - Arbeid
Type - Material: SS 2343 Rustfritt stål, prosessrør, generisk
Pset_DistributionFlowElementCommon - Reference: nk-50-250263; sets with these values: 2
Group: 38= VanGen 12; 38= VanGen 10
Name (nk-50-250263:nk-50-250263:...)
2575566
2575646
2593074

# IfcFlowFitting: Overganger, konsentriske, rustfritt EN 1,4307304L:Standard (20)
Type - Material: SS 2343 Rustfritt stål, prosessrør, generisk
Pset_DistributionFlowElementCommon - Reference: Standard; sets with these values: 2
Name (Overganger, konsentriske, rustfritt EN 1,4307304L:Standard:...) | In | Group
2596991 | Plan U2 - Arbeid | 38= VanGen 12
2658873 | Plan U1 - Arbeid | 38= VanGen 12
2662639 | Plan U1 - Arbeid | 38= VanGen 9
2663274 | Plan U1 - Arbeid | 38= VanGen 5
2664752 | Plan U1 - Arbeid | 38= VanGen 12
2665857 | Plan U1 - Arbeid | 38= VanGen 12
2665902 | Plan U1 - Arbeid | 38= VanGen 12
2667953 | Plan U1 - Arbeid | 38= VanGen 12
2670680 | Plan U1 - Arbeid | 38= VanGen 5
2671547 | Plan U1 - Arbeid | 38= VanGen 5
2672565 | Plan U1 - Arbeid | 38= VanGen 12
2672610 | Plan U1 - Arbeid | 38= VanGen 5
2673101 | Plan U2 - Arbeid | 38= VanGen 10
2679826 | Plan U2 - Arbeid | 38= VanGen 12
2679914 | Plan U2 - Arbeid | 38= VanGen 12
2686492 | Plan 01 | 38= VanGen 12
2687622 | Plan U1 - Arbeid | 38= VanGen 12
2691973 | Plan U2 - Arbeid | 38= VanGen 10
2698803 | Plan U2 - Arbeid | 38= VanGen 10
2699155 | Plan U2 - Arbeid | 38= VanGen 10

# IfcFlowFitting: T-rør,Rustfritt EN 1,4307304L, sveiste, oppkraget, metrisk, EN 10253-4:Standard (5)
Type - Material: Rustfritt
Pset_DistributionFlowElementCommon - Reference: Standard; sets with these values: 2
Name (T-rør,Rustfritt EN 1,4307304L, sveiste, oppkraget, metrisk, EN 10253-4:Standard:...) | In | NominalDiameter | Group
2552610 | Plan 01 | 150 | 38= VanGen 2
2552719 | Plan 01 | 150 | 38= VanGen 2
2606716 | Plan U1 - Arbeid | 200 | 38= VanGen 12
2607326 | Plan U1 - Arbeid | 200 | 38= VanGen 12
2626406 | Plan U1 - Arbeid | 200 | 38= VanGen 12

# IfcFlowFitting: VA_prosess_rustfritt_T_D=L:T-rør_prosess_D=L (28)
Type - Material: SS 2343 Rustfritt stål, prosessrør, generisk
Pset_DistributionFlowElementCommon - Reference: T-rør_prosess_D=L; sets with these values: 2
Name (VA_prosess_rustfritt_T_D=L:T-rør_prosess_D=L:...) | In | Group
2639571 | Plan U1 - Arbeid | 38= VanGen 12
2640558 | Plan U1 - Arbeid | 38= VanGen 2
2640846 | Plan U1 - Arbeid | 38= VanGen 2
2644982 | Plan U1 - Arbeid | 38= VanGen 12
2652849 | Plan U1 - Arbeid | 38= VanGen 12
2655387 | Plan U1 - Arbeid | 38= VanGen 14
2655410 | Plan U1 - Arbeid | 38= VanGen 14
2655644 | Plan U1 - Arbeid | 38= VanGen 14
2655673 | Plan U1 - Arbeid | 38= VanGen 14
2655702 | Plan U1 - Arbeid | 38= VanGen 14
2655731 | Plan U1 - Arbeid | 38= VanGen 14
2656183 | Plan U1 - Arbeid | 38= VanGen 37
2656189 | Plan U1 - Arbeid | 38= VanGen 37
2656201 | Plan U1 - Arbeid | 38= VanGen 37
2656205 | Plan U1 - Arbeid | 38= VanGen 37
2656209 | Plan U1 - Arbeid | 38= VanGen 37
2656213 | Plan U1 - Arbeid | 38= VanGen 37
2660876 | Plan U1 - Arbeid | 38= VanGen 12
2661098 | Plan U1 - Arbeid | 38= VanGen 12
2661276 | Plan U1 - Arbeid | 38= VanGen 12
2663120 | Plan U1 - Arbeid | 38= VanGen 9
2663153 | Plan U1 - Arbeid | 38= VanGen 9
2663312 | Plan U1 - Arbeid | 38= VanGen 5
2663333 | Plan U1 - Arbeid | 38= VanGen 5
2664062 | Plan U1 - Arbeid | 38= VanGen 2
2673212 | Plan U2 - Arbeid | 38= VanGen 10
2675234 | Plan U2 - Arbeid | 38= VanGen 10
2698856 | Plan U2 - Arbeid | 38= VanGen 10

# IfcFlowFitting: VA_prosess_rustfritt_bend_D+100:VA_prosess_rustfritt_bend_D+100 (69)
Type - Material: SS 2343 Rustfritt stål, prosessrør, generisk
Pset_DistributionFlowElementCommon - Reference: VA_prosess_rustfritt_bend_D+100; sets with these values: 2
Name (VA_prosess_rustfritt_bend_D+100:VA_prosess_rustfritt_bend_D+100:...) | In | Group
2546204 | Plan 01 | 38= VanGen 2
2546223 | Plan 01 | 38= VanGen 2
2552431 | Plan 01 | 38= VanGen 2
2552614 | Plan 01 | 38= VanGen 2
2552723 | Plan 01 | 38= VanGen 2
2591318 | Plan U2 - Arbeid | 38= VanGen 10
2614677 | Plan 01 | 38= VanGen 2
2615855 | Plan U1 - Arbeid | 38= VanGen 13
2640680 | Plan U1 - Arbeid | 38= VanGen 2
2640684 | Plan U1 - Arbeid | 38= VanGen 2
2642342 | Plan 01 | 38= VanGen 12
2643412 | Plan U1 - Arbeid | 38= VanGen 1
2643685 | Plan U1 - Arbeid | 38= VanGen 2
2644952 | Plan U1 - Arbeid | 38= VanGen 12
2650521 | Plan U1 - Arbeid | 38= VanGen 3
2650541 | Plan U1 - Arbeid | 38= VanGen 3
2655208 | Plan U1 - Arbeid | 38= VanGen 14
2655236 | Plan U1 - Arbeid | 38= VanGen 14
2656175 | Plan U1 - Arbeid | 38= VanGen 37
2656179 | Plan U1 - Arbeid | 38= VanGen 37
2656488 | Plan U1 - Arbeid | 38= VanGen 12
2658848 | Plan U2 - Arbeid | 38= VanGen 12
2660160 | Plan U1 - Arbeid | 38= VanGen 12
2660199 | Plan U1 - Arbeid | 38= VanGen 12
2660429 | Plan U1 - Arbeid | 38= VanGen 12
2662617 | Plan U1 - Arbeid | 38= VanGen 9
2663745 | Plan U1 - Arbeid | 38= VanGen 2
2664070 | Plan U1 - Arbeid | 38= VanGen 2
2668100 | Plan U1 - Arbeid | 38= VanGen 12
2668176 | Plan U1 - Arbeid | 38= VanGen 12
2668263 | Plan U1 - Arbeid | 38= VanGen 12
2669174 | Plan U1 - Arbeid | 38= VanGen 5
2669744 | Plan U1 - Arbeid | 38= VanGen 9
2675238 | Plan U2 - Arbeid | 38= VanGen 10
2681631 | Plan U1 - Arbeid | 38= VanGen 5
2681634 | Plan U1 - Arbeid | 38= VanGen 5
2682010 | Plan U1 - Arbeid | 38= VanGen 5
2682055 | Plan U1 - Arbeid | 38= VanGen 5
2683961 | Plan 01 | 38= VanGen 12
2685189 | Plan U2 - Arbeid | 38= VanGen 12
2685743 | Plan U2 - Arbeid | 38= VanGen 12
2685952 | Plan U2 - Arbeid | 38= VanGen 12
2686415 | Plan U2 - Arbeid | 38= VanGen 12
2686490 | Plan 01 | 38= VanGen 12
2687460 | Plan U1 - Arbeid | 38= VanGen 2
2687491 | Plan U1 - Arbeid | 38= VanGen 2
2688219 | Plan U1 - Arbeid | 38= VanGen 12
2688223 | Plan U1 - Arbeid | 38= VanGen 12
2688437 | Plan U1 - Arbeid | 38= VanGen 2
2689839 | Plan U1 - Arbeid | 38= VanGen 4
2690137 | Plan U1 - Arbeid | 38= VanGen 7
2693313 | Plan U1 - Arbeid | 38= VanGen 12
2694640 | Plan U2 - Arbeid | 38= VanGen 12
2696363 | Plan U1 - Arbeid | 38= VanGen 12
2697017 | Plan U1 - Arbeid | 38= VanGen 13
2697056 | Plan U1 - Arbeid | 38= VanGen 12
2697060 | Plan U1 - Arbeid | 38= VanGen 12
2697108 | Plan U1 - Arbeid | 38= VanGen 12
2699723 | Plan U1 - Arbeid | 38= VanGen 13
2699800 | Plan U1 - Arbeid | 38= VanGen 13
2699900 | Plan U1 - Arbeid | 38= VanGen 13
2700254 | Plan U1 - Arbeid | 38= VanGen 13
2700258 | Plan U1 - Arbeid | 38= VanGen 13
2700383 | Plan U2 - Arbeid | 38= VanGen 12
2700387 | Plan U2 - Arbeid | 38= VanGen 12
2700427 | Plan U2 - Arbeid | 38= VanGen 12
2700529 | Plan U1 - Arbeid | 38= VanGen 12
2700532 | Plan U2 - Arbeid | 38= VanGen 12
2701886 | Plan U2 - Arbeid | 38= VanGen 12

# IfcFlowFitting: VA_prosess_rustfritt_kryss:VA_prosess_rustfritt_kryss (20)
In: Plan U1 - Arbeid
Type - Material: SS 2343 Rustfritt stål, prosessrør, generisk
Pset_DistributionFlowElementCommon - Reference: VA_prosess_rustfritt_kryss; sets with these values: 2
Group: 38= VanGen 12
Name (VA_prosess_rustfritt_kryss:VA_prosess_rustfritt_kryss:...)
2654699
2654705
2654714
2654722
2654730
2654738
2654746
2654754
2654762
2654770
2656098
2656104
2656113
2656119
2656127
2656135
2656143
2656151
2656159
2656167

# IfcFlowFitting: VA_prosess_rustfritt_vinklet_innsveising:VA_prosess_rustfritt_vinklet_innsveising (9)
Type - Material: DF_Material1
Pset_DistributionFlowElementCommon - Reference: VA_prosess_rustfritt_vinklet_innsveising; sets with these values: 2
Name (VA_prosess_rustfritt_vinklet_innsveising:VA_prosess_rustfritt_vinklet_innsveising:...) | In | Group
2683965 | Plan 01 | 38= VanGen 12
2685428 | Plan U2 - Arbeid | 38= VanGen 12
2686092 | Plan U2 - Arbeid | 38= VanGen 12
2686098 | Plan U2 - Arbeid | 38= VanGen 12
2696457 | Plan U1 - Arbeid | 38= VanGen 12
2697110 | Plan U1 - Arbeid | 38= VanGen 12
2697216 | Plan U1 - Arbeid | 38= VanGen 13
2701949 | Plan U2 - Arbeid | 38= VanGen 12
2701954 | Plan U2 - Arbeid | 38= VanGen 12

# IfcFlowSegment: Pipe Types:AISI 304L Rustfritt (239)
Type - Material: SS 2343 Rustfritt stål, prosessrør, generisk
Pset_DistributionFlowElementCommon - Reference: AISI 304L Rustfritt; sets with these values: 2
Pset_DuctConnection - ConnectionType: Generic; sets with these values: 2
Name (Pipe Types:AISI 304L Rustfritt:...) | In | Pset_FlowSegmentDuctSegment, Length (mm) = Pset_FlowSegmentPipeSegment, Length (mm) | InvertElevation (mm) | Group
2536076 | Plan 01 | 301.831 | 19921.3 | 38= VanGen 2
2537531 | Plan U1 - Arbeid | 900 | 18425 | 38= VanGen 2
2540515 | Plan U1 - Arbeid | 1000 | 14103 | 38= VanGen 3
2544762 | Plan U2 - Arbeid | 1023.69 | 17085.7 | 38= VanGen 12
2544801 | Plan U2 - Arbeid | 4841.3 | 14118.2 | 38= VanGen 12
2544820 | Plan U2 - Arbeid | 4867.04 | 14076.9 | 38= VanGen 12
2546194 | Plan 01 | 996.261 | 18750 | 38= VanGen 2
2547577 | Plan U2 - Arbeid | 385.231 | 11170.2 | 38= VanGen 10
2547586 | Plan U2 - Arbeid | 3040 | 11170.2 | 38= VanGen 10
2547589 | Plan U2 - Arbeid | 2940 | 11170.2 | 38= VanGen 10
2552383 | Plan 01 | 301.831 | 19321.3 | 38= VanGen 2
2552391 | Plan 01 | 396.261 | 18750 | 38= VanGen 2
2552594 | Plan 01 | 409.176 | 19321.3 | 38= VanGen 2
2552600 | Plan 01 | 560.547 | 18585.7 | 38= VanGen 2
2552611 | Plan 01 | 3100 | 18425 | 38= VanGen 2
2552646 | Plan 01 | 5650 | 18425 | 38= VanGen 2
2552701 | Plan 01 | 409.176 | 19921.3 | 38= VanGen 2
2552709 | Plan 01 | 1160.55 | 18585.7 | 38= VanGen 2
2552720 | Plan U1 - Arbeid | 3100 | 18425 | 38= VanGen 2
2552744 | Plan U1 - Arbeid | 5394 | 18425 | 38= VanGen 2
2577438 | Plan U1 - Arbeid | 1322 | 14803.5 | 38= VanGen 12
2577880 | Plan U1 - Arbeid | 899.71 | 15538.3 | 38= VanGen 12
2578370 | Plan U1 - Arbeid | 886.436 | 15551 | 38= VanGen 12
2580642 | Plan U1 - Arbeid | 792 | 14103 | 38= VanGen 12
2582544 | Plan U1 - Arbeid | 1836.12 | 14205 | 38= VanGen 12
2583761 | Plan U1 - Arbeid | 3852.04 | 17628 | 38= VanGen 2
2591716 | Plan U2 - Arbeid | 718.667 | 11270.2 | 38= VanGen 10
2596068 | Plan U2 - Arbeid | 837.208 | 11702.4 | 38= VanGen 12
2597341 | Plan U2 - Arbeid | 486.692 | 11270.2 | 38= VanGen 10
2597540 | Plan U2 - Arbeid | 843.308 | 11220.2 | 38= VanGen 10
2603713 | Plan U1 - Arbeid | 1600 | 17703 | 38= VanGen 12
2603943 | Plan U1 - Arbeid | 825.38 | 17703 | 38= VanGen 12
2604006 | Plan U1 - Arbeid | 925.38 | 17703 | 38= VanGen 12
2604115 | Plan U1 - Arbeid | 1127.18 | 17703 | 38= VanGen 12
2607271 | Plan U1 - Arbeid | 1429.57 | 16452.3 | 38= VanGen 12
2607327 | Plan U1 - Arbeid | 1467.74 | 16452.3 | 38= VanGen 12
2613303 | Plan U1 - Arbeid | 1723 | 15780 | 38= VanGen 12
2614907 | Plan U1 - Arbeid | 2782.14 | 14103 | 38= VanGen 2
2615759 | Plan U1 - Arbeid | 895 | 14503 | 38= VanGen 13
2615947 | Plan U1 - Arbeid | 1017.85 | 14503 | 38= VanGen 13
2624770 | Plan U1 - Arbeid | 1073.87 | 16452.3 | 38= VanGen 12
2625059 | Plan U1 - Arbeid | 1160.3 | 14028 | 38= VanGen 12
2626285 | Plan U1 - Arbeid | 1507.71 | 14803.5 | 38= VanGen 12
2626365 | Plan U1 - Arbeid | 1467.74 | 14803.5 | 38= VanGen 12
2626407 | Plan U1 - Arbeid | 1329.57 | 14803.5 | 38= VanGen 12
2627121 | Plan U1 - Arbeid | 4629.15 | 14103 | 38= VanGen 2
2627847 | Plan U1 - Arbeid | 2572.76 | 18425 | 38= VanGen 2
2628803 | Plan U1 - Arbeid | 3572 | 14628 | 38= VanGen 2
2635917 | Plan U1 - Arbeid | 1575.84 | 14160 | 38= VanGen 9
2639572 | Plan U1 - Arbeid | 1757.1 | 14103 | 38= VanGen 12
2639667 | Plan U1 - Arbeid | 462.238 | 14103 | 38= VanGen 12
2639934 | Plan U1 - Arbeid | 2725 | 14728 | 38= VanGen 2
2640178 | Plan U1 - Arbeid | 9410 | 14103 | 38= VanGen 2
2640559 | Plan U1 - Arbeid | 347 | 18153 | 38= VanGen 2
2640941 | Plan 01 | 326.831 | 19333.8 | 38= VanGen 12
2641042 | Plan 01 | 434.176 | 19333.8 | 38= VanGen 12
2641110 | Plan 01 | 881.15 | 18290.2 | 38= VanGen 12
2642318 | Plan 01 | 806.3 | 18365 | 38= VanGen 12
2642997 | Plan U1 - Arbeid | 4610 | 18425 | 38= VanGen 2
2643010 | Plan U1 - Arbeid | 2423.86 | 18425 | 38= VanGen 2
2643394 | Plan U1 - Arbeid | 4616.29 | 14152 | 38= VanGen 1
2643402 | Plan U1 - Arbeid | 1637.45 | 14152 | 38= VanGen 1
2643476 | Plan U1 - Arbeid | 2508 | 14885 | 38= VanGen 5
2643673 | Plan U1 - Arbeid | 2170.85 | 14103 | 38= VanGen 2
2644983 | Plan U1 - Arbeid | 2480.18 | 17703 | 38= VanGen 12
2648893 | Plan U2 - Arbeid | 586.761 | 18559.5 | 38= VanGen 12
2649066 | Plan U1 - Arbeid | 716 | 18459.5 | 38= VanGen 12
2649303 | Plan U1 - Arbeid | 5817.8 | 18272 | 38= VanGen 12
2649542 | Plan U2 - Arbeid | 1093.7 | 18272 | 38= VanGen 12
2650513 | Plan U1 - Arbeid | 960 | 14103 | 38= VanGen 3
2650535 | Plan U1 - Arbeid | 1060 | 14103 | 38= VanGen 3
2653226 | Plan U1 - Arbeid | 842 | 14103 | 38= VanGen 12
2654695 | Plan U1 - Arbeid | 550 | 14163 | 38= VanGen 12
2654697 | Plan U1 - Arbeid | 550 | 14163 | 38= VanGen 12
2654701 | Plan U1 - Arbeid | 550 | 14163 | 38= VanGen 12
2654703 | Plan U1 - Arbeid | 550 | 14163 | 38= VanGen 12
2654708 | Plan U1 - Arbeid | 34 | 14103 | 38= VanGen 12
2654710 | Plan U1 - Arbeid | 550 | 14163 | 38= VanGen 12
2654712 | Plan U1 - Arbeid | 550 | 14163 | 38= VanGen 12
2654716 | Plan U1 - Arbeid | 40 | 14103 | 38= VanGen 12
2654720 | Plan U1 - Arbeid | 550 | 14163 | 38= VanGen 12
2654724 | Plan U1 - Arbeid | 40 | 14103 | 38= VanGen 12
2654726 | Plan U1 - Arbeid | 550 | 14163 | 38= VanGen 12
2654728 | Plan U1 - Arbeid | 550 | 14163 | 38= VanGen 12
2654732 | Plan U1 - Arbeid | 40 | 14103 | 38= VanGen 12
2654734 | Plan U1 - Arbeid | 550 | 14163 | 38= VanGen 12
2654736 | Plan U1 - Arbeid | 550 | 14163 | 38= VanGen 12
2654740 | Plan U1 - Arbeid | 40 | 14103 | 38= VanGen 12
2654742 | Plan U1 - Arbeid | 550 | 14163 | 38= VanGen 12
2654744 | Plan U1 - Arbeid | 550 | 14163 | 38= VanGen 12
2654748 | Plan U1 - Arbeid | 40 | 14103 | 38= VanGen 12
2654750 | Plan U1 - Arbeid | 550 | 14163 | 38= VanGen 12
2654752 | Plan U1 - Arbeid | 550 | 14163 | 38= VanGen 12
2654756 | Plan U1 - Arbeid | 40 | 14103 | 38= VanGen 12
2654758 | Plan U1 - Arbeid | 550 | 14163 | 38= VanGen 12
2654760 | Plan U1 - Arbeid | 550 | 14163 | 38= VanGen 12
2654764 | Plan U1 - Arbeid | 40 | 14103 | 38= VanGen 12
2654766 | Plan U1 - Arbeid | 550 | 14163 | 38= VanGen 12
2654768 | Plan U1 - Arbeid | 550 | 14163 | 38= VanGen 12
2654772 | Plan U1 - Arbeid | 40 | 14103 | 38= VanGen 12
2655186 | Plan U1 - Arbeid | 30 | 14475 | 38= VanGen 14
2655197 | Plan U1 - Arbeid | 4130 | 14475 | 38= VanGen 14
2655221 | Plan U1 - Arbeid | 4130 | 14475 | 38= VanGen 14
2655376 | Plan U1 - Arbeid | 4230 | 14475 | 38= VanGen 14
2655388 | Plan U1 - Arbeid | 30 | 14475 | 38= VanGen 14
2655402 | Plan U1 - Arbeid | 4230 | 14475 | 38= VanGen 14
2655411 | Plan U1 - Arbeid | 130 | 14475 | 38= VanGen 14
2655483 | Plan U1 - Arbeid | 4230 | 14475 | 38= VanGen 14
2655506 | Plan U1 - Arbeid | 4230 | 14475 | 38= VanGen 14
2655525 | Plan U1 - Arbeid | 4230 | 14475 | 38= VanGen 14
2655542 | Plan U1 - Arbeid | 4230 | 14475 | 38= VanGen 14
2655645 | Plan U1 - Arbeid | 130 | 14475 | 38= VanGen 14
2655674 | Plan U1 - Arbeid | 130 | 14475 | 38= VanGen 14
2655703 | Plan U1 - Arbeid | 130 | 14475 | 38= VanGen 14
2655732 | Plan U1 - Arbeid | 130 | 14475 | 38= VanGen 14
2656094 | Plan U1 - Arbeid | 550 | 14163 | 38= VanGen 12
2656096 | Plan U1 - Arbeid | 550 | 14163 | 38= VanGen 12
2656100 | Plan U1 - Arbeid | 550 | 14163 | 38= VanGen 12
2656102 | Plan U1 - Arbeid | 550 | 14163 | 38= VanGen 12
2656107 | Plan U1 - Arbeid | 34 | 14103 | 38= VanGen 12
2656109 | Plan U1 - Arbeid | 550 | 14163 | 38= VanGen 12
2656111 | Plan U1 - Arbeid | 550 | 14163 | 38= VanGen 12
2656115 | Plan U1 - Arbeid | 40 | 14103 | 38= VanGen 12
2656117 | Plan U1 - Arbeid | 550 | 14163 | 38= VanGen 12
2656121 | Plan U1 - Arbeid | 40 | 14103 | 38= VanGen 12
2656123 | Plan U1 - Arbeid | 550 | 14163 | 38= VanGen 12
2656125 | Plan U1 - Arbeid | 550 | 14163 | 38= VanGen 12
2656129 | Plan U1 - Arbeid | 40 | 14103 | 38= VanGen 12
2656131 | Plan U1 - Arbeid | 550 | 14163 | 38= VanGen 12
2656133 | Plan U1 - Arbeid | 550 | 14163 | 38= VanGen 12
2656137 | Plan U1 - Arbeid | 40 | 14103 | 38= VanGen 12
2656139 | Plan U1 - Arbeid | 550 | 14163 | 38= VanGen 12
2656141 | Plan U1 - Arbeid | 550 | 14163 | 38= VanGen 12
2656145 | Plan U1 - Arbeid | 40 | 14103 | 38= VanGen 12
2656147 | Plan U1 - Arbeid | 550 | 14163 | 38= VanGen 12
2656149 | Plan U1 - Arbeid | 550 | 14163 | 38= VanGen 12
2656153 | Plan U1 - Arbeid | 40 | 14103 | 38= VanGen 12
2656155 | Plan U1 - Arbeid | 550 | 14163 | 38= VanGen 12
2656157 | Plan U1 - Arbeid | 550 | 14163 | 38= VanGen 12
2656161 | Plan U1 - Arbeid | 40 | 14103 | 38= VanGen 12
2656163 | Plan U1 - Arbeid | 550 | 14163 | 38= VanGen 12
2656165 | Plan U1 - Arbeid | 550 | 14163 | 38= VanGen 12
2656169 | Plan U1 - Arbeid | 40 | 14103 | 38= VanGen 12
2656171 | Plan U1 - Arbeid | 30 | 14475 | 38= VanGen 37
2656173 | Plan U1 - Arbeid | 4130 | 14475 | 38= VanGen 37
2656177 | Plan U1 - Arbeid | 4130 | 14475 | 38= VanGen 37
2656181 | Plan U1 - Arbeid | 4230 | 14475 | 38= VanGen 37
2656184 | Plan U1 - Arbeid | 30 | 14475 | 38= VanGen 37
2656187 | Plan U1 - Arbeid | 4230 | 14475 | 38= VanGen 37
2656190 | Plan U1 - Arbeid | 130 | 14475 | 38= VanGen 37
2656193 | Plan U1 - Arbeid | 4230 | 14475 | 38= VanGen 37
2656195 | Plan U1 - Arbeid | 4230 | 14475 | 38= VanGen 37
2656197 | Plan U1 - Arbeid | 4230 | 14475 | 38= VanGen 37
2656199 | Plan U1 - Arbeid | 4230 | 14475 | 38= VanGen 37
2656202 | Plan U1 - Arbeid | 130 | 14475 | 38= VanGen 37
2656206 | Plan U1 - Arbeid | 130 | 14475 | 38= VanGen 37
2656210 | Plan U1 - Arbeid | 130 | 14475 | 38= VanGen 37
2656214 | Plan U1 - Arbeid | 130 | 14475 | 38= VanGen 37
2656677 | Plan U1 - Arbeid | 550 | 14163 | 38= VanGen 12
2656702 | Plan U1 - Arbeid | 550 | 14163 | 38= VanGen 12
2660152 | Plan U1 - Arbeid | 1749.3 | 14503 | 38= VanGen 12
2660877 | Plan U1 - Arbeid | 575 | 17703 | 38= VanGen 12
2661255 | Plan U1 - Arbeid | 2404.5 | 15805 | 38= VanGen 12
2661263 | Plan U1 - Arbeid | 1763 | 15517.5 | 38= VanGen 12
2661277 | Plan U1 - Arbeid | 977 | 14403 | 38= VanGen 12
2662609 | Plan U1 - Arbeid | 71.0036 | 14160 | 38= VanGen 9
2662619 | Plan U1 - Arbeid | 330 | 14210 | 38= VanGen 9
2662662 | Plan U1 - Arbeid | 398.489 | 14210 | 38= VanGen 9
2662991 | Plan U1 - Arbeid | 398.478 | 14210 | 38= VanGen 9
2663053 | Plan U1 - Arbeid | 398.467 | 14210 | 38= VanGen 9
2663121 | Plan U1 - Arbeid | 677.517 | 14160 | 38= VanGen 9
2663154 | Plan U1 - Arbeid | 311.479 | 14160 | 38= VanGen 9
2663266 | Plan U1 - Arbeid | 160 | 14935 | 38= VanGen 5
2663276 | Plan U1 - Arbeid | 150 | 14485 | 38= VanGen 5
2663299 | Plan U1 - Arbeid | 70 | 14715 | 38= VanGen 5
2663313 | Plan U1 - Arbeid | 241.004 | 14885 | 38= VanGen 5
2663322 | Plan U1 - Arbeid | 70.0002 | 14714.9 | 38= VanGen 5
2663334 | Plan U1 - Arbeid | 677.517 | 14885 | 38= VanGen 5
2664040 | Plan U1 - Arbeid | 3622 | 14628 | 38= VanGen 2
2664063 | Plan U1 - Arbeid | 117.856 | 14103 | 38= VanGen 2
2664733 | Plan U1 - Arbeid | 35.8825 | 15262.8 | 38= VanGen 12
2665847 | Plan U1 - Arbeid | 135.41 | 14753.5 | 38= VanGen 12
2665892 | Plan U1 - Arbeid | 142.397 | 14753.5 | 38= VanGen 12
2667935 | Plan U1 - Arbeid | 60 | 14255 | 38= VanGen 12
2668036 | Plan U1 - Arbeid | 76.7407 | 15109.7 | 38= VanGen 12
2668130 | Plan U1 - Arbeid | 13.429 | 15461.5 | 38= VanGen 12
2668214 | Plan U1 - Arbeid | 533.465 | 14653 | 38= VanGen 12
2668222 | Plan U1 - Arbeid | 170.31 | 14028 | 38= VanGen 12
2670665 | Plan U1 - Arbeid | 80 | 14485 | 38= VanGen 5
2671532 | Plan U1 - Arbeid | 80 | 14485 | 38= VanGen 5
2672550 | Plan U1 - Arbeid | 40 | 14780 | 38= VanGen 12
2673213 | Plan U2 - Arbeid | 678.131 | 11220.2 | 38= VanGen 10
2674205 | Plan U2 - Arbeid | 36.197 | 11545.2 | 38= VanGen 12
2674287 | Plan U2 - Arbeid | 36.2052 | 11545.2 | 38= VanGen 12
2675235 | Plan U2 - Arbeid | 549.684 | 11170.2 | 38= VanGen 10
2678810 | Plan U1 - Arbeid | 3293.95 | 16452.3 | 38= VanGen 12
2679422 | Plan U2 - Arbeid | 408.74 | 12268.3 | 38= VanGen 12
2679887 | Plan U2 - Arbeid | 253.338 | 11702.4 | 38= VanGen 12
2681463 | Plan U1 - Arbeid | 1318.48 | 14885 | 38= VanGen 5
2681469 | Plan U1 - Arbeid | 2607.64 | 14885 | 38= VanGen 5
2682002 | Plan U1 - Arbeid | 182.012 | 14503 | 38= VanGen 5
2682047 | Plan U1 - Arbeid | 2145 | 14103 | 38= VanGen 5
2683953 | Plan U1 - Arbeid | 3253.4 | 18040 | 38= VanGen 12
2683966 | Plan U1 - Arbeid | 2962.4 | 18040 | 38= VanGen 12
2684362 | Plan U2 - Arbeid | 953.808 | 12989.6 | 38= VanGen 12
2685375 | Plan U2 - Arbeid | 1717.46 | 12702.1 | 38= VanGen 12
2685596 | Plan U2 - Arbeid | 283.695 | 12118.2 | 38= VanGen 12
2685735 | Plan U2 - Arbeid | 21.3241 | 12118.2 | 38= VanGen 12
2686093 | Plan U2 - Arbeid | 390.777 | 11702.4 | 38= VanGen 12
2686099 | Plan U2 - Arbeid | 3697.45 | 12118.2 | 38= VanGen 12
2686295 | Plan U2 - Arbeid | 1578.94 | 12405.7 | 38= VanGen 12
2686656 | Plan U1 - Arbeid | 1162.6 | 16677.4 | 38= VanGen 12
2687347 | Plan U2 - Arbeid | 36.197 | 11545.2 | 38= VanGen 12
2687612 | Plan U1 - Arbeid | 22.6 | 15263.5 | 38= VanGen 12
2688169 | Plan U1 - Arbeid | 34.8249 | 15517.5 | 38= VanGen 12
2688772 | Plan U1 - Arbeid | 2444 | 13797 | 38= VanGen 13
2689823 | Plan U1 - Arbeid | 2353.3 | 17500 | 38= VanGen 4
2689831 | Plan U1 - Arbeid | 1106 | 20003.3 | 38= VanGen 4
2690133 | Plan U1 - Arbeid | 2353.3 | 17500 | 38= VanGen 7
2690135 | Plan U1 - Arbeid | 1071.37 | 20003.3 | 38= VanGen 7
2691334 | Plan U2 - Arbeid | 10270 | 11170.2 | 38= VanGen 10
2691846 | Plan U2 - Arbeid | 379.284 | 11270.2 | 38= VanGen 10
2691959 | Plan U2 - Arbeid | 418.673 | 11270.2 | 38= VanGen 10
2694143 | Plan U2 - Arbeid | 997.187 | 17112.3 | 38= VanGen 12
2696448 | Plan U1 - Arbeid | 1421.22 | 14028 | 38= VanGen 12
2696458 | Plan U1 - Arbeid | 2405 | 14028 | 38= VanGen 12
2696830 | Plan U1 - Arbeid | 4841.42 | 14197 | 38= VanGen 13
2697009 | Plan 01 | 300 | 19238.4 | 38= VanGen 13
2697111 | Plan U1 - Arbeid | 1223.7 | 15203.5 | 38= VanGen 12
2697217 | Plan U1 - Arbeid | 1674.9 | 14503 | 38= VanGen 13
2697363 | Plan U1 - Arbeid | 271.9 | 14503 | 38= VanGen 13
2699792 | Plan U1 - Arbeid | 10994 | 13797 | 38= VanGen 13
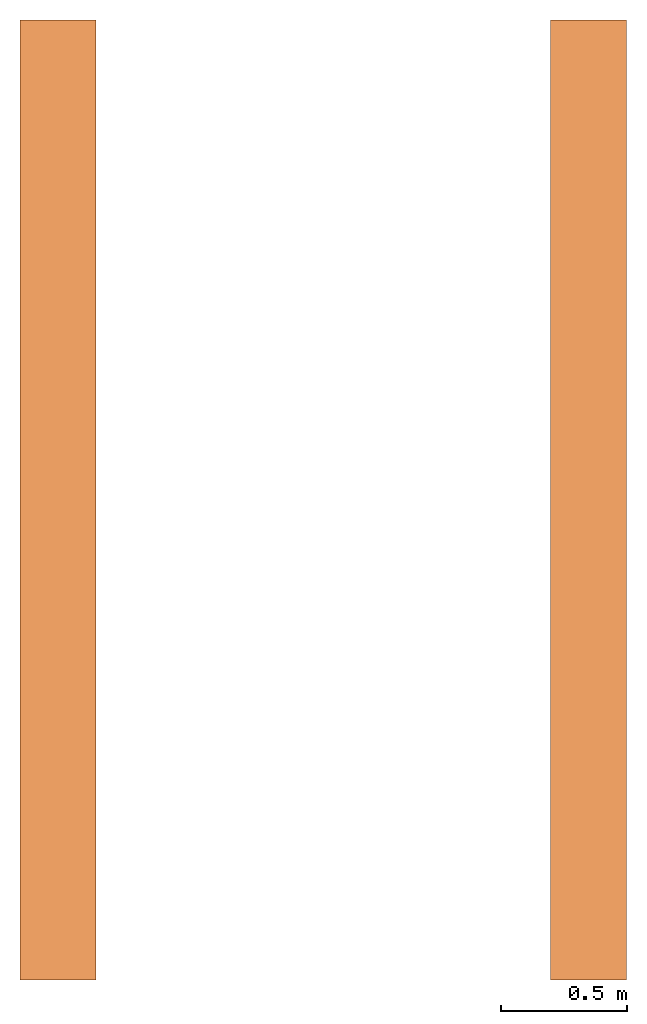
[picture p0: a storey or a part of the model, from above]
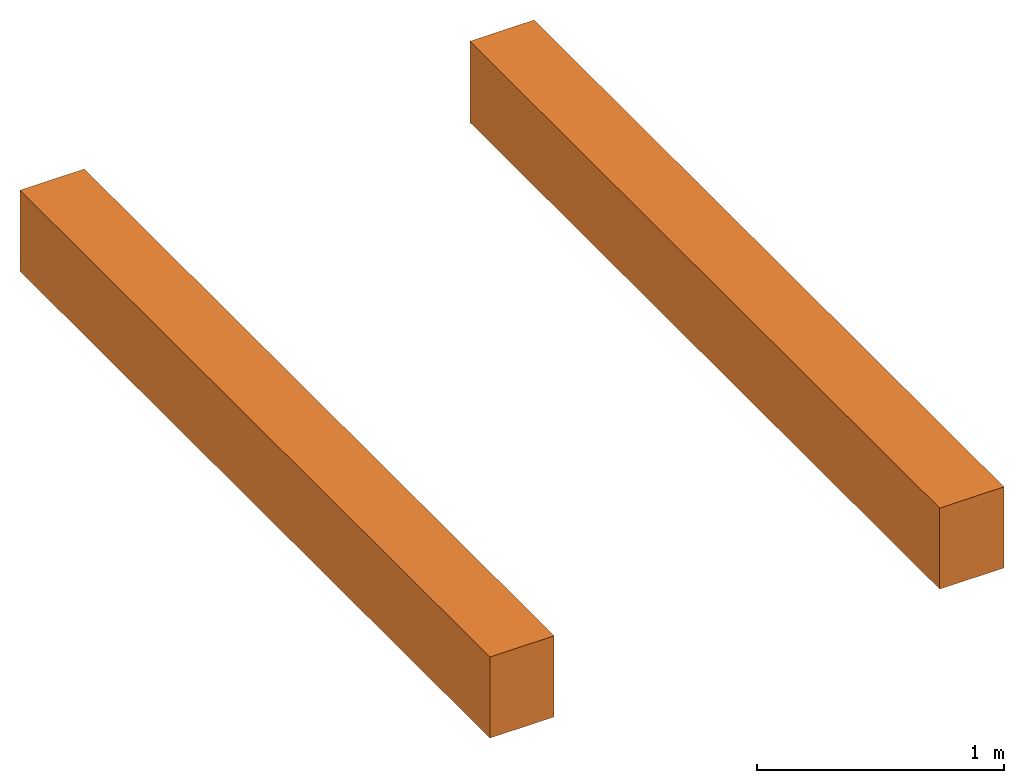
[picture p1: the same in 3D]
Properties of the parts of a building model (IFC2X3), part 2 of 2

# IfcFlowSegment: Pipe Types:AISI 304L Rustfritt (239)
Name (Pipe Types:AISI 304L Rustfritt:...) | In | Pset_FlowSegmentDuctSegment, Length (mm) = Pset_FlowSegmentPipeSegment, Length (mm) | InvertElevation (mm) | Group
2700201 | Plan U1 - Arbeid | 106 | 14197 | 38= VanGen 13
2700209 | Plan U1 - Arbeid | 5113 | 14503 | 38= VanGen 13
2701537 | Plan U2 - Arbeid | 362.977 | 12118.2 | 38= VanGen 12
2701914 | Plan U2 - Arbeid | 567.448 | 12210.9 | 38= VanGen 12
2701923 | Plan U2 - Arbeid | 362.352 | 12702.1 | 38= VanGen 12
2701950 | Plan U2 - Arbeid | 362.76 | 12702.1 | 38= VanGen 12
2701955 | Plan U2 - Arbeid | 362.776 | 12118.2 | 38= VanGen 12

# IfcMember: Stringer:Stringer - 50 mm Width (30)
Type - PredefinedType: STRINGER
Material: <Unnamed>
Pset_MemberCommon - IsExternal: no; Reference: Stringer - 50 mm Width
Pset_QuantityTakeOff - Reference: Stringer - 50 mm Width
Name (Assembled Stair:Stair:...) | In | Slope (deg)
2490742 Stringer 1 | Plan U2 - Arbeid | 32.2213
2490742 Stringer 2 | Plan U2 - Arbeid | 32.2213
2490742 Stringer 3 | Plan U2 - Arbeid | 32.2213
2490742 Stringer 4 | Plan U2 - Arbeid | 32.2213
2490742 Stringer 5 | Plan U2 - Arbeid | 0
2490742 Stringer 6 | Plan U2 - Arbeid | 0
2490742 Stringer 7 | Plan U2 - Arbeid | 0
2490742 Stringer 9 | Plan U2 - Arbeid | 0
2492616 Stringer 1 | Plan U1 - Arbeid | 32.5279
2492616 Stringer 2 | Plan U1 - Arbeid | 32.5279
2492616 Stringer 3 | Plan U1 - Arbeid | 32.5279
2492616 Stringer 4 | Plan U1 - Arbeid | 32.5279
2492616 Stringer 5 | Plan U1 - Arbeid | 0
2492616 Stringer 6 | Plan U1 - Arbeid | 0
2492616 Stringer 7 | Plan U1 - Arbeid | 0
2492616 Stringer 8 | Plan U1 - Arbeid | 0
2492616 Stringer 10 | Plan U1 - Arbeid | 32.5279
2492616 Stringer 11 | Plan U1 - Arbeid | 32.5279
2492616 Stringer 12 | Plan U1 - Arbeid | 0
2492616 Stringer 13 | Plan U1 - Arbeid | 0
2492616 Stringer 14 | Plan U1 - Arbeid | 0
2492616 Stringer 15 | Plan U1 - Arbeid | 0
2492616 Stringer 16 | Plan U1 - Arbeid | 0
2492616 Stringer 17 | Plan U1 - Arbeid | 32.5279
2492616 Stringer 18 | Plan U1 - Arbeid | 32.5279
2492616 Stringer 19 | Plan U1 - Arbeid | 0
2492616 Stringer 20 | Plan U1 - Arbeid | 0
2492616 Stringer 21 | Plan U1 - Arbeid | 0
2492616 Stringer 23 | Plan U1 - Arbeid | 0
2492616 Stringer 25 | Plan U1 - Arbeid | 73.736

# IfcOpeningElement: Opening (33)
In: Plan 01
Name
5 x Floor:Generic 200mm:2119699 | Pset_OpeningElementCommon - Reference: Generic 200mm; sets with these values: 2
Basic Wall:Generic - 300mm:2422939 | Pset_OpeningElementCommon - Reference: 986 x 2089 mm - M10 x M21; sets with these values: 2; Pset_FireRatingProperties - FireResistanceRating: EI60 (BD60)
Garage dooor/gate:2600x2400mm:2499129:1
Awning Casement double:1200/1200:2448676:1
Awning Casement double:1800/1200:2448495:1
Awning Casement double:1800/1200:2508589:1
Garage dooor/gate:3000x3600mm 3:2422937:1
Single Door Simple:986 x 2089 mm - M10 x M21:2429828:1
Single Door Simple:986 x 2089 mm - M10 x M21:2454157:1
Awning Casement double:1200/1200:2480331:1
Single Door Simple:986 x 2089 mm - M10 x M21:2432838:1
Double Door Simple:1930mm x 2184mm - ion alu:2422955:1
Single Door Simple:986 x 2089 mm - M10 x M21:2433603:1
Double Door Simple:1930mm x 2184mm - ion alu:2433673:1
Single Door Simple:986 x 2089 mm - M10 x M21:2497734:1
Single Door Simple:986 x 2089 mm - M10 x M21:2429803:1
Single Door Simple:886 x 2089 mm - M9 x M21:2429868:1
Single Door Simple:986 x 2089 mm - M10 x M21:2432875:1
Single Door Simple:886 x 2089 mm - M9 x M21:2432924:1
Single Door Simple:986 x 2089 mm - M10 x M21:2432963:1
Single Door Simple:886 x 2089 mm - M9 x M21:2432995:1
Single Door Simple:886 x 2089 mm - M9 x M21:2507334:1
Single Door Simple:986 x 2089 mm - M10 x M21:2496062:1
Single Door Simple:986 x 2089 mm - M10 x M21:2496106:1
Single Door Simple:986 x 2089 mm - M10 x M21:2498785:1
Single Door Simple:886 x 2089 mm - M9 x M21:2502379:1
Awning Casement double:1200/1200:2507214:1
Awning Casement double:1800/1200:2507095:1
Awning Casement double:1800/1200:2508533:1

# IfcRailing: Railing:1100mm (5)
Material: <Unnamed>
Pset_QuantityTakeOff - Reference: 1100mm
Pset_RailingCommon - IsExternal: no; Reference: 1100mm; Height: 1219.2 mm
Name (Railing:1100mm:...) | In
2452839 | Plan U1 - Arbeid
2491376 | Plan U2 - Arbeid
2491380 | Plan U2 - Arbeid
2493516 | Plan U1 - Arbeid
2494563 | Plan 01

# IfcRoof: Basic Roof:Generic - 400mm, Basic Roof:Generic - 400mm:2464510
In: Plan Tak Høy
Material: Default Roof 400 mm
Pset_QuantityTakeOff - Reference: Generic - 400mm
Pset_RoofCommon - IsExternal: yes; Reference: Generic - 400mm; ProjectedArea: 476.145 m2; TotalArea: 507.772 m2

# IfcSlab: Floor:Generic 200mm (5)
Type - PredefinedType: FLOOR; Material: Default Floor 200 mm
Pset_QuantityTakeOff - Reference: Generic 200mm; sets with these values: 2
Pset_SlabCommon - Reference: Generic 200mm; IsExternal: no; PitchAngle: 0 deg
Name (Floor:Generic 200mm:...) | In | LoadBearing
2422918 | Plan 01 | yes
2423414 | Plan U1 - Arbeid | yes
2423510 | Plan U2 - Arbeid | yes
2509511 | Plan 01 | no
2510914 | Plan 01 | yes

# IfcSlab: Non-Monolithic Landing:Non-Monolithic Landing (4)
Type - PredefinedType: LANDING
Material: <Unnamed>
Pset_QuantityTakeOff - Reference: Non-Monolithic Landing; sets with these values: 2
Pset_SlabCommon - IsExternal: no; Reference: Non-Monolithic Landing
Name (Assembled Stair:Stair:...) | In
2490742 Landing 1 | Plan U2 - Arbeid
2492616 Landing 1 | Plan U1 - Arbeid
2492616 Landing 2 | Plan U1 - Arbeid
2492616 Landing 3 | Plan U1 - Arbeid

# IfcStair: Assembled Stair:Stairs 1 (2)
Pset_QuantityTakeOff - Reference: Stairs 1
Pset_StairCommon - IsExternal: no; Reference: Stairs 1; TreadLength: 280 mm
Name (Assembled Stair:Stair:...) | In | NumberOfRiser | NumberOfTreads | RiserHeight (mm)
2490742 | Plan U2 - Arbeid | 17 | 15 | 176.471 | ShapeType: HALF_TURN_STAIR
2492616 | Plan U1 - Arbeid | 28 | 24 | 178.571

# IfcStairFlight: Non-Monolithic Run:50 mm Tread 10 mm Riser (6)
Type - PredefinedType: STRAIGHT
Type - Pset_StairFlightCommon - NosingLength: 0 mm
TreadLength: 0.918635 mm; Material: <Unnamed>
Pset_QuantityTakeOff - Reference: 50 mm Tread 10 mm Riser
Pset_StairFlightCommon - Reference: 50 mm Tread 10 mm Riser; TreadLength: 280 mm; WalkingLineOffset: 1.47638 mm; TreadLengthAtOffset: 280 mm; TreadLengthAtInnerSide: 280 mm
Name (Assembled Stair:Stair:...) | In | NumberOfRiser = Pset_StairFlightCommon, NumberOfRiser | NumberOfTreads = Pset_StairFlightCommon, NumberOfTreads | RiserHeight (mm) | Pset_StairFlightCommon, RiserHeight (mm)
2490742 Run 1 | Plan U2 - Arbeid | 13 | 12 | 0.578972 | 176.471
2490742 Run 2 | Plan U2 - Arbeid | 4 | 3 | 0.578972 | 176.471
2492616 Run 1 | Plan U1 - Arbeid | 7 | 6 | 0.585864 | 178.571
2492616 Run 2 | Plan U1 - Arbeid | 7 | 6 | 0.585864 | 178.571
2492616 Run 3 | Plan U1 - Arbeid | 7 | 6 | 0.585864 | 178.571
2492616 Run 4 | Plan U1 - Arbeid | 7 | 6 | 0.585864 | 178.571

# IfcWallStandardCase: Basic Wall:Generic - 100mm (9)
In: Plan 01
Type - PredefinedType: STANDARD; Material: Default Wall 100 mm
Pset_QuantityTakeOff - Reference: Generic - 100mm; sets with these values: 2
Pset_WallCommon - IsExternal: yes; LoadBearing: no; ExtendToStructure: no; Reference: Generic - 100mm
Name (Basic Wall:Generic - 100mm:...)
2428843
2429039
2429173
2429265
2429591
2429653
2429978
2502252
2502966

# IfcWallStandardCase: Basic Wall:Generic - 150mm, Basic Wall:Generic - 150mm:2510593
In: Plan 01
Type - PredefinedType: STANDARD; Material: Default Wall 150 mm
Pset_QuantityTakeOff - Reference: Generic - 150mm; sets with these values: 2
Pset_WallCommon - IsExternal: yes; ExtendToStructure: yes; LoadBearing: yes; Reference: Generic - 150mm

# IfcWallStandardCase: Basic Wall:Generic - 200mm (10)
In: Plan 01
Type - PredefinedType: STANDARD; Material: Default Wall 200 mm
Pset_QuantityTakeOff - Reference: Generic - 200mm; sets with these values: 2
Pset_WallCommon - IsExternal: yes; LoadBearing: no; Reference: Generic - 200mm
Name (Basic Wall:Generic - 200mm:...) | ExtendToStructure
2422907 | no
2422927 | yes
2422942 | yes
2422943 | yes
2422946 | yes
2422982 | yes
2472937 | no
2497428 | no
2497641 | yes
2501934 | yes

# IfcWallStandardCase: Basic Wall:Generic - 300mm (26)
Type - PredefinedType: STANDARD; Material: Default Wall 300 mm
Pset_QuantityTakeOff - Reference: Generic - 300mm; sets with these values: 2
Pset_WallCommon - Reference: Generic - 300mm; IsExternal: yes
Name (Basic Wall:Generic - 300mm:...) | In | ExtendToStructure | LoadBearing
2422903 | Plan 01 | yes | no
2422904 | Plan 01 | yes | no
2422905 | Plan 01 | yes | no
2422906 | Plan 01 | yes | no
2422939 | Plan 01 | yes | no
2423399 | Plan U1 - Arbeid | yes | no
2423400 | Plan U1 - Arbeid | yes | no
2423403 | Plan U1 - Arbeid | yes | no
2423404 | Plan U1 - Arbeid | yes | no
2423405 | Plan U1 - Arbeid | yes | no
2423406 | Plan U1 - Arbeid | yes | no
2423423 | Plan U1 - Arbeid | yes | no
2423426 | Plan U1 - Arbeid | yes | no
2423516 | Plan U2 - Arbeid | no | yes
2423517 | Plan U2 - Arbeid | no | yes
2423518 | Plan U2 - Arbeid | no | yes
2423519 | Plan U2 - Arbeid | no | yes
2425741 | Plan U1 - Arbeid | yes | no
2432429 | Plan U1 - Arbeid | yes | no
2434745 | Plan 01 | yes | no
2436752 | Plan U2 - Arbeid | no | yes
2437110 | Plan U2 - Arbeid | no | yes
2498706 | Plan 01 | yes | no
2506742 | Plan 01 | yes | no
2506888 | Plan 01 | yes | no
2540409 | Plan U1 - Arbeid | no | yes

# IfcWallStandardCase: Basic Wall:Generic Luft - 100mm 2, Basic Wall:Generic Luft - 100mm 2:2499257
In: Plan 01
Type - PredefinedType: STANDARD; Material: SS 2333 Rustfritt stål - sveiste rør 300 mm
Pset_QuantityTakeOff - Reference: Generic Luft - 100mm 2; sets with these values: 2
Pset_WallCommon - IsExternal: yes; LoadBearing: no; ExtendToStructure: no; Reference: Generic Luft - 100mm 2

# IfcWindow: Awning Casement double:1200/1200 (3)
In: Plan 01
Type - OperationType: DOUBLE_PANEL_VERTICAL; ParameterTakesPrecedence: no; Sizeable: no; Material: Glass, Default Frame, Default Sill
OverallHeight: 1200 mm; OverallWidth: 1200 mm
Pset_QuantityTakeOff - Reference: 1200/1200
Pset_WindowCommon - IsExternal: yes; Reference: 1200/1200
Name (Awning Casement double:1200/1200:...)
2448676
2480331
2507214

# IfcWindow: Awning Casement double:1800/1200 (4)
In: Plan 01
Type - OperationType: DOUBLE_PANEL_VERTICAL; ParameterTakesPrecedence: no; Sizeable: no; Material: Glass, Default Frame, Default Sill
OverallHeight: 1200 mm; OverallWidth: 1800 mm
Pset_QuantityTakeOff - Reference: 1800/1200
Pset_WindowCommon - IsExternal: yes; Reference: 1800/1200
Name (Awning Casement double:1800/1200:...)
2448495
2507095
2508533
2508589
